VERSION 5.7 ;
BUSBITCHARS "[]" ;
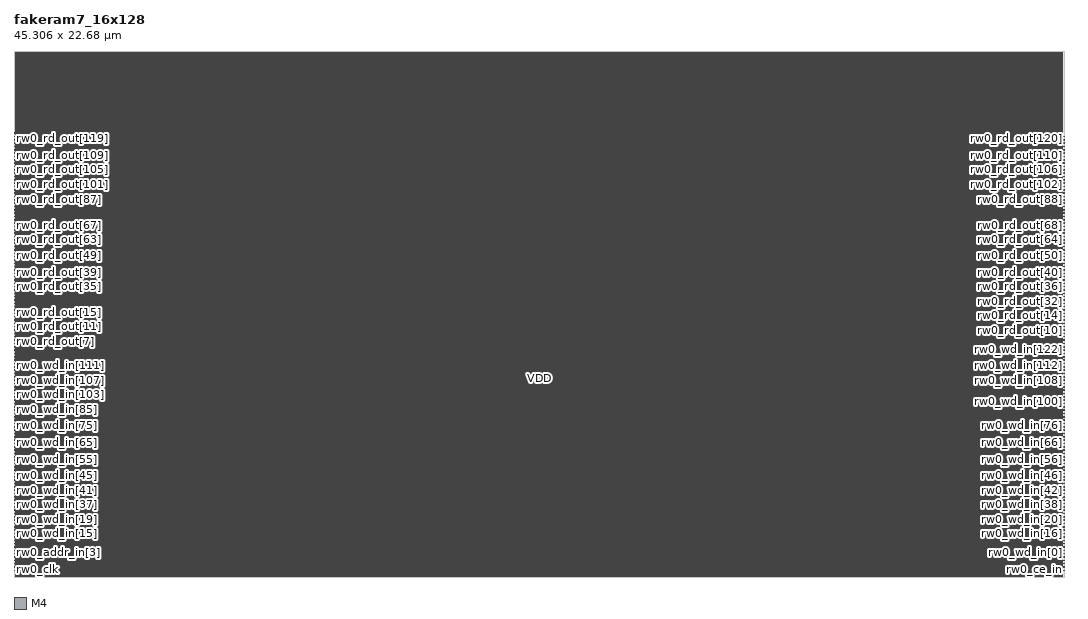
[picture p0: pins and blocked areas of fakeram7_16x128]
MACRO fakeram7_16x128
  FOREIGN fakeram7_16x128 0 0 ;
  SYMMETRY X Y R90 ;
  SIZE 45.306 BY 22.680 ;
  CLASS BLOCK ;
  PIN rw0_clk
    DIRECTION INPUT ;
    USE SIGNAL ;
    SHAPE ABUTMENT ;
    PORT
      LAYER M4 ;
      RECT 0.000 0.276 0.072 0.300 ;
    END
  END rw0_clk
  PIN rw0_ce_in
    DIRECTION INPUT ;
    USE SIGNAL ;
    SHAPE ABUTMENT ;
    PORT
      LAYER M4 ;
      RECT 45.234 0.276 45.306 0.300 ;
    END
  END rw0_ce_in
  PIN rw0_we_in
    DIRECTION INPUT ;
    USE SIGNAL ;
    SHAPE ABUTMENT ;
    PORT
      LAYER M4 ;
      RECT 0.000 0.420 0.072 0.444 ;
    END
  END rw0_we_in
  PIN rw0_addr_in[0]
    DIRECTION INPUT ;
    USE SIGNAL ;
    SHAPE ABUTMENT ;
    PORT
      LAYER M4 ;
      RECT 45.234 0.420 45.306 0.444 ;
    END
  END rw0_addr_in[0]
  PIN rw0_addr_in[1]
    DIRECTION INPUT ;
    USE SIGNAL ;
    SHAPE ABUTMENT ;
    PORT
      LAYER M4 ;
      RECT 0.000 0.564 0.072 0.588 ;
    END
  END rw0_addr_in[1]
  PIN rw0_addr_in[2]
    DIRECTION INPUT ;
    USE SIGNAL ;
    SHAPE ABUTMENT ;
    PORT
      LAYER M4 ;
      RECT 45.234 0.564 45.306 0.588 ;
    END
  END rw0_addr_in[2]
  PIN rw0_addr_in[3]
    DIRECTION INPUT ;
    USE SIGNAL ;
    SHAPE ABUTMENT ;
    PORT
      LAYER M4 ;
      RECT 0.000 0.708 0.072 0.732 ;
    END
  END rw0_addr_in[3]
  PIN rw0_wd_in[0]
    DIRECTION INPUT ;
    USE SIGNAL ;
    SHAPE ABUTMENT ;
    PORT
      LAYER M4 ;
      RECT 45.234 0.708 45.306 0.732 ;
    END
  END rw0_wd_in[0]
  PIN rw0_wd_in[1]
    DIRECTION INPUT ;
    USE SIGNAL ;
    SHAPE ABUTMENT ;
    PORT
      LAYER M4 ;
      RECT 0.000 0.852 0.072 0.876 ;
    END
  END rw0_wd_in[1]
  PIN rw0_wd_in[2]
    DIRECTION INPUT ;
    USE SIGNAL ;
    SHAPE ABUTMENT ;
    PORT
      LAYER M4 ;
      RECT 45.234 0.852 45.306 0.876 ;
    END
  END rw0_wd_in[2]
  PIN rw0_wd_in[3]
    DIRECTION INPUT ;
    USE SIGNAL ;
    SHAPE ABUTMENT ;
    PORT
      LAYER M4 ;
      RECT 0.000 0.996 0.072 1.020 ;
    END
  END rw0_wd_in[3]
  PIN rw0_wd_in[4]
    DIRECTION INPUT ;
    USE SIGNAL ;
    SHAPE ABUTMENT ;
    PORT
      LAYER M4 ;
      RECT 45.234 0.996 45.306 1.020 ;
    END
  END rw0_wd_in[4]
  PIN rw0_wd_in[5]
    DIRECTION INPUT ;
    USE SIGNAL ;
    SHAPE ABUTMENT ;
    PORT
      LAYER M4 ;
      RECT 0.000 1.140 0.072 1.164 ;
    END
  END rw0_wd_in[5]
  PIN rw0_wd_in[6]
    DIRECTION INPUT ;
    USE SIGNAL ;
    SHAPE ABUTMENT ;
    PORT
      LAYER M4 ;
      RECT 45.234 1.140 45.306 1.164 ;
    END
  END rw0_wd_in[6]
  PIN rw0_wd_in[7]
    DIRECTION INPUT ;
    USE SIGNAL ;
    SHAPE ABUTMENT ;
    PORT
      LAYER M4 ;
      RECT 0.000 1.284 0.072 1.308 ;
    END
  END rw0_wd_in[7]
  PIN rw0_wd_in[8]
    DIRECTION INPUT ;
    USE SIGNAL ;
    SHAPE ABUTMENT ;
    PORT
      LAYER M4 ;
      RECT 45.234 1.284 45.306 1.308 ;
    END
  END rw0_wd_in[8]
  PIN rw0_wd_in[9]
    DIRECTION INPUT ;
    USE SIGNAL ;
    SHAPE ABUTMENT ;
    PORT
      LAYER M4 ;
      RECT 0.000 1.428 0.072 1.452 ;
    END
  END rw0_wd_in[9]
  PIN rw0_wd_in[10]
    DIRECTION INPUT ;
    USE SIGNAL ;
    SHAPE ABUTMENT ;
    PORT
      LAYER M4 ;
      RECT 45.234 1.428 45.306 1.452 ;
    END
  END rw0_wd_in[10]
  PIN rw0_wd_in[11]
    DIRECTION INPUT ;
    USE SIGNAL ;
    SHAPE ABUTMENT ;
    PORT
      LAYER M4 ;
      RECT 0.000 1.572 0.072 1.596 ;
    END
  END rw0_wd_in[11]
  PIN rw0_wd_in[12]
    DIRECTION INPUT ;
    USE SIGNAL ;
    SHAPE ABUTMENT ;
    PORT
      LAYER M4 ;
      RECT 45.234 1.572 45.306 1.596 ;
    END
  END rw0_wd_in[12]
  PIN rw0_wd_in[13]
    DIRECTION INPUT ;
    USE SIGNAL ;
    SHAPE ABUTMENT ;
    PORT
      LAYER M4 ;
      RECT 0.000 1.716 0.072 1.740 ;
    END
  END rw0_wd_in[13]
  PIN rw0_wd_in[14]
    DIRECTION INPUT ;
    USE SIGNAL ;
    SHAPE ABUTMENT ;
    PORT
      LAYER M4 ;
      RECT 45.234 1.716 45.306 1.740 ;
    END
  END rw0_wd_in[14]
  PIN rw0_wd_in[15]
    DIRECTION INPUT ;
    USE SIGNAL ;
    SHAPE ABUTMENT ;
    PORT
      LAYER M4 ;
      RECT 0.000 1.860 0.072 1.884 ;
    END
  END rw0_wd_in[15]
  PIN rw0_wd_in[16]
    DIRECTION INPUT ;
    USE SIGNAL ;
    SHAPE ABUTMENT ;
    PORT
      LAYER M4 ;
      RECT 45.234 1.860 45.306 1.884 ;
    END
  END rw0_wd_in[16]
  PIN rw0_wd_in[17]
    DIRECTION INPUT ;
    USE SIGNAL ;
    SHAPE ABUTMENT ;
    PORT
      LAYER M4 ;
      RECT 0.000 2.004 0.072 2.028 ;
    END
  END rw0_wd_in[17]
  PIN rw0_wd_in[18]
    DIRECTION INPUT ;
    USE SIGNAL ;
    SHAPE ABUTMENT ;
    PORT
      LAYER M4 ;
      RECT 45.234 2.004 45.306 2.028 ;
    END
  END rw0_wd_in[18]
  PIN rw0_wd_in[19]
    DIRECTION INPUT ;
    USE SIGNAL ;
    SHAPE ABUTMENT ;
    PORT
      LAYER M4 ;
      RECT 0.000 2.148 0.072 2.172 ;
    END
  END rw0_wd_in[19]
  PIN rw0_wd_in[20]
    DIRECTION INPUT ;
    USE SIGNAL ;
    SHAPE ABUTMENT ;
    PORT
      LAYER M4 ;
      RECT 45.234 2.148 45.306 2.172 ;
    END
  END rw0_wd_in[20]
  PIN rw0_wd_in[21]
    DIRECTION INPUT ;
    USE SIGNAL ;
    SHAPE ABUTMENT ;
    PORT
      LAYER M4 ;
      RECT 0.000 2.292 0.072 2.316 ;
    END
  END rw0_wd_in[21]
  PIN rw0_wd_in[22]
    DIRECTION INPUT ;
    USE SIGNAL ;
    SHAPE ABUTMENT ;
    PORT
      LAYER M4 ;
      RECT 45.234 2.292 45.306 2.316 ;
    END
  END rw0_wd_in[22]
  PIN rw0_wd_in[23]
    DIRECTION INPUT ;
    USE SIGNAL ;
    SHAPE ABUTMENT ;
    PORT
      LAYER M4 ;
      RECT 0.000 2.436 0.072 2.460 ;
    END
  END rw0_wd_in[23]
  PIN rw0_wd_in[24]
    DIRECTION INPUT ;
    USE SIGNAL ;
    SHAPE ABUTMENT ;
    PORT
      LAYER M4 ;
      RECT 45.234 2.436 45.306 2.460 ;
    END
  END rw0_wd_in[24]
  PIN rw0_wd_in[25]
    DIRECTION INPUT ;
    USE SIGNAL ;
    SHAPE ABUTMENT ;
    PORT
      LAYER M4 ;
      RECT 0.000 2.580 0.072 2.604 ;
    END
  END rw0_wd_in[25]
  PIN rw0_wd_in[26]
    DIRECTION INPUT ;
    USE SIGNAL ;
    SHAPE ABUTMENT ;
    PORT
      LAYER M4 ;
      RECT 45.234 2.580 45.306 2.604 ;
    END
  END rw0_wd_in[26]
  PIN rw0_wd_in[27]
    DIRECTION INPUT ;
    USE SIGNAL ;
    SHAPE ABUTMENT ;
    PORT
      LAYER M4 ;
      RECT 0.000 2.724 0.072 2.748 ;
    END
  END rw0_wd_in[27]
  PIN rw0_wd_in[28]
    DIRECTION INPUT ;
    USE SIGNAL ;
    SHAPE ABUTMENT ;
    PORT
      LAYER M4 ;
      RECT 45.234 2.724 45.306 2.748 ;
    END
  END rw0_wd_in[28]
  PIN rw0_wd_in[29]
    DIRECTION INPUT ;
    USE SIGNAL ;
    SHAPE ABUTMENT ;
    PORT
      LAYER M4 ;
      RECT 0.000 2.868 0.072 2.892 ;
    END
  END rw0_wd_in[29]
  PIN rw0_wd_in[30]
    DIRECTION INPUT ;
    USE SIGNAL ;
    SHAPE ABUTMENT ;
    PORT
      LAYER M4 ;
      RECT 45.234 2.868 45.306 2.892 ;
    END
  END rw0_wd_in[30]
  PIN rw0_wd_in[31]
    DIRECTION INPUT ;
    USE SIGNAL ;
    SHAPE ABUTMENT ;
    PORT
      LAYER M4 ;
      RECT 0.000 3.012 0.072 3.036 ;
    END
  END rw0_wd_in[31]
  PIN rw0_wd_in[32]
    DIRECTION INPUT ;
    USE SIGNAL ;
    SHAPE ABUTMENT ;
    PORT
      LAYER M4 ;
      RECT 45.234 3.012 45.306 3.036 ;
    END
  END rw0_wd_in[32]
  PIN rw0_wd_in[33]
    DIRECTION INPUT ;
    USE SIGNAL ;
    SHAPE ABUTMENT ;
    PORT
      LAYER M4 ;
      RECT 0.000 3.156 0.072 3.180 ;
    END
  END rw0_wd_in[33]
  PIN rw0_wd_in[34]
    DIRECTION INPUT ;
    USE SIGNAL ;
    SHAPE ABUTMENT ;
    PORT
      LAYER M4 ;
      RECT 45.234 3.156 45.306 3.180 ;
    END
  END rw0_wd_in[34]
  PIN rw0_wd_in[35]
    DIRECTION INPUT ;
    USE SIGNAL ;
    SHAPE ABUTMENT ;
    PORT
      LAYER M4 ;
      RECT 0.000 3.300 0.072 3.324 ;
    END
  END rw0_wd_in[35]
  PIN rw0_wd_in[36]
    DIRECTION INPUT ;
    USE SIGNAL ;
    SHAPE ABUTMENT ;
    PORT
      LAYER M4 ;
      RECT 45.234 3.300 45.306 3.324 ;
    END
  END rw0_wd_in[36]
  PIN rw0_wd_in[37]
    DIRECTION INPUT ;
    USE SIGNAL ;
    SHAPE ABUTMENT ;
    PORT
      LAYER M4 ;
      RECT 0.000 3.444 0.072 3.468 ;
    END
  END rw0_wd_in[37]
  PIN rw0_wd_in[38]
    DIRECTION INPUT ;
    USE SIGNAL ;
    SHAPE ABUTMENT ;
    PORT
      LAYER M4 ;
      RECT 45.234 3.444 45.306 3.468 ;
    END
  END rw0_wd_in[38]
  PIN rw0_wd_in[39]
    DIRECTION INPUT ;
    USE SIGNAL ;
    SHAPE ABUTMENT ;
    PORT
      LAYER M4 ;
      RECT 0.000 3.588 0.072 3.612 ;
    END
  END rw0_wd_in[39]
  PIN rw0_wd_in[40]
    DIRECTION INPUT ;
    USE SIGNAL ;
    SHAPE ABUTMENT ;
    PORT
      LAYER M4 ;
      RECT 45.234 3.588 45.306 3.612 ;
    END
  END rw0_wd_in[40]
  PIN rw0_wd_in[41]
    DIRECTION INPUT ;
    USE SIGNAL ;
    SHAPE ABUTMENT ;
    PORT
      LAYER M4 ;
      RECT 0.000 3.732 0.072 3.756 ;
    END
  END rw0_wd_in[41]
  PIN rw0_wd_in[42]
    DIRECTION INPUT ;
    USE SIGNAL ;
    SHAPE ABUTMENT ;
    PORT
      LAYER M4 ;
      RECT 45.234 3.732 45.306 3.756 ;
    END
  END rw0_wd_in[42]
  PIN rw0_wd_in[43]
    DIRECTION INPUT ;
    USE SIGNAL ;
    SHAPE ABUTMENT ;
    PORT
      LAYER M4 ;
      RECT 0.000 3.876 0.072 3.900 ;
    END
  END rw0_wd_in[43]
  PIN rw0_wd_in[44]
    DIRECTION INPUT ;
    USE SIGNAL ;
    SHAPE ABUTMENT ;
    PORT
      LAYER M4 ;
      RECT 45.234 3.876 45.306 3.900 ;
    END
  END rw0_wd_in[44]
  PIN rw0_wd_in[45]
    DIRECTION INPUT ;
    USE SIGNAL ;
    SHAPE ABUTMENT ;
    PORT
      LAYER M4 ;
      RECT 0.000 4.020 0.072 4.044 ;
    END
  END rw0_wd_in[45]
  PIN rw0_wd_in[46]
    DIRECTION INPUT ;
    USE SIGNAL ;
    SHAPE ABUTMENT ;
    PORT
      LAYER M4 ;
      RECT 45.234 4.020 45.306 4.044 ;
    END
  END rw0_wd_in[46]
  PIN rw0_wd_in[47]
    DIRECTION INPUT ;
    USE SIGNAL ;
    SHAPE ABUTMENT ;
    PORT
      LAYER M4 ;
      RECT 0.000 4.164 0.072 4.188 ;
    END
  END rw0_wd_in[47]
  PIN rw0_wd_in[48]
    DIRECTION INPUT ;
    USE SIGNAL ;
    SHAPE ABUTMENT ;
    PORT
      LAYER M4 ;
      RECT 45.234 4.164 45.306 4.188 ;
    END
  END rw0_wd_in[48]
  PIN rw0_wd_in[49]
    DIRECTION INPUT ;
    USE SIGNAL ;
    SHAPE ABUTMENT ;
    PORT
      LAYER M4 ;
      RECT 0.000 4.308 0.072 4.332 ;
    END
  END rw0_wd_in[49]
  PIN rw0_wd_in[50]
    DIRECTION INPUT ;
    USE SIGNAL ;
    SHAPE ABUTMENT ;
    PORT
      LAYER M4 ;
      RECT 45.234 4.308 45.306 4.332 ;
    END
  END rw0_wd_in[50]
  PIN rw0_wd_in[51]
    DIRECTION INPUT ;
    USE SIGNAL ;
    SHAPE ABUTMENT ;
    PORT
      LAYER M4 ;
      RECT 0.000 4.452 0.072 4.476 ;
    END
  END rw0_wd_in[51]
  PIN rw0_wd_in[52]
    DIRECTION INPUT ;
    USE SIGNAL ;
    SHAPE ABUTMENT ;
    PORT
      LAYER M4 ;
      RECT 45.234 4.452 45.306 4.476 ;
    END
  END rw0_wd_in[52]
  PIN rw0_wd_in[53]
    DIRECTION INPUT ;
    USE SIGNAL ;
    SHAPE ABUTMENT ;
    PORT
      LAYER M4 ;
      RECT 0.000 4.596 0.072 4.620 ;
    END
  END rw0_wd_in[53]
  PIN rw0_wd_in[54]
    DIRECTION INPUT ;
    USE SIGNAL ;
    SHAPE ABUTMENT ;
    PORT
      LAYER M4 ;
      RECT 45.234 4.596 45.306 4.620 ;
    END
  END rw0_wd_in[54]
  PIN rw0_wd_in[55]
    DIRECTION INPUT ;
    USE SIGNAL ;
    SHAPE ABUTMENT ;
    PORT
      LAYER M4 ;
      RECT 0.000 4.740 0.072 4.764 ;
    END
  END rw0_wd_in[55]
  PIN rw0_wd_in[56]
    DIRECTION INPUT ;
    USE SIGNAL ;
    SHAPE ABUTMENT ;
    PORT
      LAYER M4 ;
      RECT 45.234 4.740 45.306 4.764 ;
    END
  END rw0_wd_in[56]
  PIN rw0_wd_in[57]
    DIRECTION INPUT ;
    USE SIGNAL ;
    SHAPE ABUTMENT ;
    PORT
      LAYER M4 ;
      RECT 0.000 4.884 0.072 4.908 ;
    END
  END rw0_wd_in[57]
  PIN rw0_wd_in[58]
    DIRECTION INPUT ;
    USE SIGNAL ;
    SHAPE ABUTMENT ;
    PORT
      LAYER M4 ;
      RECT 45.234 4.884 45.306 4.908 ;
    END
  END rw0_wd_in[58]
  PIN rw0_wd_in[59]
    DIRECTION INPUT ;
    USE SIGNAL ;
    SHAPE ABUTMENT ;
    PORT
      LAYER M4 ;
      RECT 0.000 5.028 0.072 5.052 ;
    END
  END rw0_wd_in[59]
  PIN rw0_wd_in[60]
    DIRECTION INPUT ;
    USE SIGNAL ;
    SHAPE ABUTMENT ;
    PORT
      LAYER M4 ;
      RECT 45.234 5.028 45.306 5.052 ;
    END
  END rw0_wd_in[60]
  PIN rw0_wd_in[61]
    DIRECTION INPUT ;
    USE SIGNAL ;
    SHAPE ABUTMENT ;
    PORT
      LAYER M4 ;
      RECT 0.000 5.172 0.072 5.196 ;
    END
  END rw0_wd_in[61]
  PIN rw0_wd_in[62]
    DIRECTION INPUT ;
    USE SIGNAL ;
    SHAPE ABUTMENT ;
    PORT
      LAYER M4 ;
      RECT 45.234 5.172 45.306 5.196 ;
    END
  END rw0_wd_in[62]
  PIN rw0_wd_in[63]
    DIRECTION INPUT ;
    USE SIGNAL ;
    SHAPE ABUTMENT ;
    PORT
      LAYER M4 ;
      RECT 0.000 5.316 0.072 5.340 ;
    END
  END rw0_wd_in[63]
  PIN rw0_wd_in[64]
    DIRECTION INPUT ;
    USE SIGNAL ;
    SHAPE ABUTMENT ;
    PORT
      LAYER M4 ;
      RECT 45.234 5.316 45.306 5.340 ;
    END
  END rw0_wd_in[64]
  PIN rw0_wd_in[65]
    DIRECTION INPUT ;
    USE SIGNAL ;
    SHAPE ABUTMENT ;
    PORT
      LAYER M4 ;
      RECT 0.000 5.460 0.072 5.484 ;
    END
  END rw0_wd_in[65]
  PIN rw0_wd_in[66]
    DIRECTION INPUT ;
    USE SIGNAL ;
    SHAPE ABUTMENT ;
    PORT
      LAYER M4 ;
      RECT 45.234 5.460 45.306 5.484 ;
    END
  END rw0_wd_in[66]
  PIN rw0_wd_in[67]
    DIRECTION INPUT ;
    USE SIGNAL ;
    SHAPE ABUTMENT ;
    PORT
      LAYER M4 ;
      RECT 0.000 5.604 0.072 5.628 ;
    END
  END rw0_wd_in[67]
  PIN rw0_wd_in[68]
    DIRECTION INPUT ;
    USE SIGNAL ;
    SHAPE ABUTMENT ;
    PORT
      LAYER M4 ;
      RECT 45.234 5.604 45.306 5.628 ;
    END
  END rw0_wd_in[68]
  PIN rw0_wd_in[69]
    DIRECTION INPUT ;
    USE SIGNAL ;
    SHAPE ABUTMENT ;
    PORT
      LAYER M4 ;
      RECT 0.000 5.748 0.072 5.772 ;
    END
  END rw0_wd_in[69]
  PIN rw0_wd_in[70]
    DIRECTION INPUT ;
    USE SIGNAL ;
    SHAPE ABUTMENT ;
    PORT
      LAYER M4 ;
      RECT 45.234 5.748 45.306 5.772 ;
    END
  END rw0_wd_in[70]
  PIN rw0_wd_in[71]
    DIRECTION INPUT ;
    USE SIGNAL ;
    SHAPE ABUTMENT ;
    PORT
      LAYER M4 ;
      RECT 0.000 5.892 0.072 5.916 ;
    END
  END rw0_wd_in[71]
  PIN rw0_wd_in[72]
    DIRECTION INPUT ;
    USE SIGNAL ;
    SHAPE ABUTMENT ;
    PORT
      LAYER M4 ;
      RECT 45.234 5.892 45.306 5.916 ;
    END
  END rw0_wd_in[72]
  PIN rw0_wd_in[73]
    DIRECTION INPUT ;
    USE SIGNAL ;
    SHAPE ABUTMENT ;
    PORT
      LAYER M4 ;
      RECT 0.000 6.036 0.072 6.060 ;
    END
  END rw0_wd_in[73]
  PIN rw0_wd_in[74]
    DIRECTION INPUT ;
    USE SIGNAL ;
    SHAPE ABUTMENT ;
    PORT
      LAYER M4 ;
      RECT 45.234 6.036 45.306 6.060 ;
    END
  END rw0_wd_in[74]
  PIN rw0_wd_in[75]
    DIRECTION INPUT ;
    USE SIGNAL ;
    SHAPE ABUTMENT ;
    PORT
      LAYER M4 ;
      RECT 0.000 6.180 0.072 6.204 ;
    END
  END rw0_wd_in[75]
  PIN rw0_wd_in[76]
    DIRECTION INPUT ;
    USE SIGNAL ;
    SHAPE ABUTMENT ;
    PORT
      LAYER M4 ;
      RECT 45.234 6.180 45.306 6.204 ;
    END
  END rw0_wd_in[76]
  PIN rw0_wd_in[77]
    DIRECTION INPUT ;
    USE SIGNAL ;
    SHAPE ABUTMENT ;
    PORT
      LAYER M4 ;
      RECT 0.000 6.324 0.072 6.348 ;
    END
  END rw0_wd_in[77]
  PIN rw0_wd_in[78]
    DIRECTION INPUT ;
    USE SIGNAL ;
    SHAPE ABUTMENT ;
    PORT
      LAYER M4 ;
      RECT 45.234 6.324 45.306 6.348 ;
    END
  END rw0_wd_in[78]
  PIN rw0_wd_in[79]
    DIRECTION INPUT ;
    USE SIGNAL ;
    SHAPE ABUTMENT ;
    PORT
      LAYER M4 ;
      RECT 0.000 6.468 0.072 6.492 ;
    END
  END rw0_wd_in[79]
  PIN rw0_wd_in[80]
    DIRECTION INPUT ;
    USE SIGNAL ;
    SHAPE ABUTMENT ;
    PORT
      LAYER M4 ;
      RECT 45.234 6.468 45.306 6.492 ;
    END
  END rw0_wd_in[80]
  PIN rw0_wd_in[81]
    DIRECTION INPUT ;
    USE SIGNAL ;
    SHAPE ABUTMENT ;
    PORT
      LAYER M4 ;
      RECT 0.000 6.612 0.072 6.636 ;
    END
  END rw0_wd_in[81]
  PIN rw0_wd_in[82]
    DIRECTION INPUT ;
    USE SIGNAL ;
    SHAPE ABUTMENT ;
    PORT
      LAYER M4 ;
      RECT 45.234 6.612 45.306 6.636 ;
    END
  END rw0_wd_in[82]
  PIN rw0_wd_in[83]
    DIRECTION INPUT ;
    USE SIGNAL ;
    SHAPE ABUTMENT ;
    PORT
      LAYER M4 ;
      RECT 0.000 6.756 0.072 6.780 ;
    END
  END rw0_wd_in[83]
  PIN rw0_wd_in[84]
    DIRECTION INPUT ;
    USE SIGNAL ;
    SHAPE ABUTMENT ;
    PORT
      LAYER M4 ;
      RECT 45.234 6.756 45.306 6.780 ;
    END
  END rw0_wd_in[84]
  PIN rw0_wd_in[85]
    DIRECTION INPUT ;
    USE SIGNAL ;
    SHAPE ABUTMENT ;
    PORT
      LAYER M4 ;
      RECT 0.000 6.900 0.072 6.924 ;
    END
  END rw0_wd_in[85]
  PIN rw0_wd_in[86]
    DIRECTION INPUT ;
    USE SIGNAL ;
    SHAPE ABUTMENT ;
    PORT
      LAYER M4 ;
      RECT 45.234 6.900 45.306 6.924 ;
    END
  END rw0_wd_in[86]
  PIN rw0_wd_in[87]
    DIRECTION INPUT ;
    USE SIGNAL ;
    SHAPE ABUTMENT ;
    PORT
      LAYER M4 ;
      RECT 0.000 7.044 0.072 7.068 ;
    END
  END rw0_wd_in[87]
  PIN rw0_wd_in[88]
    DIRECTION INPUT ;
    USE SIGNAL ;
    SHAPE ABUTMENT ;
    PORT
      LAYER M4 ;
      RECT 45.234 7.044 45.306 7.068 ;
    END
  END rw0_wd_in[88]
  PIN rw0_wd_in[89]
    DIRECTION INPUT ;
    USE SIGNAL ;
    SHAPE ABUTMENT ;
    PORT
      LAYER M4 ;
      RECT 0.000 7.188 0.072 7.212 ;
    END
  END rw0_wd_in[89]
  PIN rw0_wd_in[90]
    DIRECTION INPUT ;
    USE SIGNAL ;
    SHAPE ABUTMENT ;
    PORT
      LAYER M4 ;
      RECT 45.234 7.188 45.306 7.212 ;
    END
  END rw0_wd_in[90]
  PIN rw0_wd_in[91]
    DIRECTION INPUT ;
    USE SIGNAL ;
    SHAPE ABUTMENT ;
    PORT
      LAYER M4 ;
      RECT 0.000 7.332 0.072 7.356 ;
    END
  END rw0_wd_in[91]
  PIN rw0_wd_in[92]
    DIRECTION INPUT ;
    USE SIGNAL ;
    SHAPE ABUTMENT ;
    PORT
      LAYER M4 ;
      RECT 45.234 7.332 45.306 7.356 ;
    END
  END rw0_wd_in[92]
  PIN rw0_wd_in[93]
    DIRECTION INPUT ;
    USE SIGNAL ;
    SHAPE ABUTMENT ;
    PORT
      LAYER M4 ;
      RECT 0.000 7.476 0.072 7.500 ;
    END
  END rw0_wd_in[93]
  PIN rw0_wd_in[94]
    DIRECTION INPUT ;
    USE SIGNAL ;
    SHAPE ABUTMENT ;
    PORT
      LAYER M4 ;
      RECT 45.234 7.476 45.306 7.500 ;
    END
  END rw0_wd_in[94]
  PIN rw0_wd_in[95]
    DIRECTION INPUT ;
    USE SIGNAL ;
    SHAPE ABUTMENT ;
    PORT
      LAYER M4 ;
      RECT 0.000 7.620 0.072 7.644 ;
    END
  END rw0_wd_in[95]
  PIN rw0_wd_in[96]
    DIRECTION INPUT ;
    USE SIGNAL ;
    SHAPE ABUTMENT ;
    PORT
      LAYER M4 ;
      RECT 45.234 7.620 45.306 7.644 ;
    END
  END rw0_wd_in[96]
  PIN rw0_wd_in[97]
    DIRECTION INPUT ;
    USE SIGNAL ;
    SHAPE ABUTMENT ;
    PORT
      LAYER M4 ;
      RECT 0.000 7.764 0.072 7.788 ;
    END
  END rw0_wd_in[97]
  PIN rw0_wd_in[98]
    DIRECTION INPUT ;
    USE SIGNAL ;
    SHAPE ABUTMENT ;
    PORT
      LAYER M4 ;
      RECT 45.234 7.764 45.306 7.788 ;
    END
  END rw0_wd_in[98]
  PIN rw0_wd_in[99]
    DIRECTION INPUT ;
    USE SIGNAL ;
    SHAPE ABUTMENT ;
    PORT
      LAYER M4 ;
      RECT 0.000 7.908 0.072 7.932 ;
    END
  END rw0_wd_in[99]
  PIN rw0_wd_in[100]
    DIRECTION INPUT ;
    USE SIGNAL ;
    SHAPE ABUTMENT ;
    PORT
      LAYER M4 ;
      RECT 45.234 7.908 45.306 7.932 ;
    END
  END rw0_wd_in[100]
  PIN rw0_wd_in[101]
    DIRECTION INPUT ;
    USE SIGNAL ;
    SHAPE ABUTMENT ;
    PORT
      LAYER M4 ;
      RECT 0.000 8.052 0.072 8.076 ;
    END
  END rw0_wd_in[101]
  PIN rw0_wd_in[102]
    DIRECTION INPUT ;
    USE SIGNAL ;
    SHAPE ABUTMENT ;
    PORT
      LAYER M4 ;
      RECT 45.234 8.052 45.306 8.076 ;
    END
  END rw0_wd_in[102]
  PIN rw0_wd_in[103]
    DIRECTION INPUT ;
    USE SIGNAL ;
    SHAPE ABUTMENT ;
    PORT
      LAYER M4 ;
      RECT 0.000 8.196 0.072 8.220 ;
    END
  END rw0_wd_in[103]
  PIN rw0_wd_in[104]
    DIRECTION INPUT ;
    USE SIGNAL ;
    SHAPE ABUTMENT ;
    PORT
      LAYER M4 ;
      RECT 45.234 8.196 45.306 8.220 ;
    END
  END rw0_wd_in[104]
  PIN rw0_wd_in[105]
    DIRECTION INPUT ;
    USE SIGNAL ;
    SHAPE ABUTMENT ;
    PORT
      LAYER M4 ;
      RECT 0.000 8.340 0.072 8.364 ;
    END
  END rw0_wd_in[105]
  PIN rw0_wd_in[106]
    DIRECTION INPUT ;
    USE SIGNAL ;
    SHAPE ABUTMENT ;
    PORT
      LAYER M4 ;
      RECT 45.234 8.340 45.306 8.364 ;
    END
  END rw0_wd_in[106]
  PIN rw0_wd_in[107]
    DIRECTION INPUT ;
    USE SIGNAL ;
    SHAPE ABUTMENT ;
    PORT
      LAYER M4 ;
      RECT 0.000 8.484 0.072 8.508 ;
    END
  END rw0_wd_in[107]
  PIN rw0_wd_in[108]
    DIRECTION INPUT ;
    USE SIGNAL ;
    SHAPE ABUTMENT ;
    PORT
      LAYER M4 ;
      RECT 45.234 8.484 45.306 8.508 ;
    END
  END rw0_wd_in[108]
  PIN rw0_wd_in[109]
    DIRECTION INPUT ;
    USE SIGNAL ;
    SHAPE ABUTMENT ;
    PORT
      LAYER M4 ;
      RECT 0.000 8.628 0.072 8.652 ;
    END
  END rw0_wd_in[109]
  PIN rw0_wd_in[110]
    DIRECTION INPUT ;
    USE SIGNAL ;
    SHAPE ABUTMENT ;
    PORT
      LAYER M4 ;
      RECT 45.234 8.628 45.306 8.652 ;
    END
  END rw0_wd_in[110]
  PIN rw0_wd_in[111]
    DIRECTION INPUT ;
    USE SIGNAL ;
    SHAPE ABUTMENT ;
    PORT
      LAYER M4 ;
      RECT 0.000 8.772 0.072 8.796 ;
    END
  END rw0_wd_in[111]
  PIN rw0_wd_in[112]
    DIRECTION INPUT ;
    USE SIGNAL ;
    SHAPE ABUTMENT ;
    PORT
      LAYER M4 ;
      RECT 45.234 8.772 45.306 8.796 ;
    END
  END rw0_wd_in[112]
  PIN rw0_wd_in[113]
    DIRECTION INPUT ;
    USE SIGNAL ;
    SHAPE ABUTMENT ;
    PORT
      LAYER M4 ;
      RECT 0.000 8.916 0.072 8.940 ;
    END
  END rw0_wd_in[113]
  PIN rw0_wd_in[114]
    DIRECTION INPUT ;
    USE SIGNAL ;
    SHAPE ABUTMENT ;
    PORT
      LAYER M4 ;
      RECT 45.234 8.916 45.306 8.940 ;
    END
  END rw0_wd_in[114]
  PIN rw0_wd_in[115]
    DIRECTION INPUT ;
    USE SIGNAL ;
    SHAPE ABUTMENT ;
    PORT
      LAYER M4 ;
      RECT 0.000 9.060 0.072 9.084 ;
    END
  END rw0_wd_in[115]
  PIN rw0_wd_in[116]
    DIRECTION INPUT ;
    USE SIGNAL ;
    SHAPE ABUTMENT ;
    PORT
      LAYER M4 ;
      RECT 45.234 9.060 45.306 9.084 ;
    END
  END rw0_wd_in[116]
  PIN rw0_wd_in[117]
    DIRECTION INPUT ;
    USE SIGNAL ;
    SHAPE ABUTMENT ;
    PORT
      LAYER M4 ;
      RECT 0.000 9.204 0.072 9.228 ;
    END
  END rw0_wd_in[117]
  PIN rw0_wd_in[118]
    DIRECTION INPUT ;
    USE SIGNAL ;
    SHAPE ABUTMENT ;
    PORT
      LAYER M4 ;
      RECT 45.234 9.204 45.306 9.228 ;
    END
  END rw0_wd_in[118]
  PIN rw0_wd_in[119]
    DIRECTION INPUT ;
    USE SIGNAL ;
    SHAPE ABUTMENT ;
    PORT
      LAYER M4 ;
      RECT 0.000 9.348 0.072 9.372 ;
    END
  END rw0_wd_in[119]
  PIN rw0_wd_in[120]
    DIRECTION INPUT ;
    USE SIGNAL ;
    SHAPE ABUTMENT ;
    PORT
      LAYER M4 ;
      RECT 45.234 9.348 45.306 9.372 ;
    END
  END rw0_wd_in[120]
  PIN rw0_wd_in[121]
    DIRECTION INPUT ;
    USE SIGNAL ;
    SHAPE ABUTMENT ;
    PORT
      LAYER M4 ;
      RECT 0.000 9.492 0.072 9.516 ;
    END
  END rw0_wd_in[121]
  PIN rw0_wd_in[122]
    DIRECTION INPUT ;
    USE SIGNAL ;
    SHAPE ABUTMENT ;
    PORT
      LAYER M4 ;
      RECT 45.234 9.492 45.306 9.516 ;
    END
  END rw0_wd_in[122]
  PIN rw0_wd_in[123]
    DIRECTION INPUT ;
    USE SIGNAL ;
    SHAPE ABUTMENT ;
    PORT
      LAYER M4 ;
      RECT 0.000 9.636 0.072 9.660 ;
    END
  END rw0_wd_in[123]
  PIN rw0_wd_in[124]
    DIRECTION INPUT ;
    USE SIGNAL ;
    SHAPE ABUTMENT ;
    PORT
      LAYER M4 ;
      RECT 45.234 9.636 45.306 9.660 ;
    END
  END rw0_wd_in[124]
  PIN rw0_wd_in[125]
    DIRECTION INPUT ;
    USE SIGNAL ;
    SHAPE ABUTMENT ;
    PORT
      LAYER M4 ;
      RECT 0.000 9.780 0.072 9.804 ;
    END
  END rw0_wd_in[125]
  PIN rw0_wd_in[126]
    DIRECTION INPUT ;
    USE SIGNAL ;
    SHAPE ABUTMENT ;
    PORT
      LAYER M4 ;
      RECT 45.234 9.780 45.306 9.804 ;
    END
  END rw0_wd_in[126]
  PIN rw0_wd_in[127]
    DIRECTION INPUT ;
    USE SIGNAL ;
    SHAPE ABUTMENT ;
    PORT
      LAYER M4 ;
      RECT 0.000 9.924 0.072 9.948 ;
    END
  END rw0_wd_in[127]
  PIN rw0_rd_out[0]
    DIRECTION OUTPUT ;
    USE SIGNAL ;
    SHAPE ABUTMENT ;
    PORT
      LAYER M4 ;
      RECT 45.234 9.924 45.306 9.948 ;
    END
  END rw0_rd_out[0]
  PIN rw0_rd_out[1]
    DIRECTION OUTPUT ;
    USE SIGNAL ;
    SHAPE ABUTMENT ;
    PORT
      LAYER M4 ;
      RECT 0.000 10.068 0.072 10.092 ;
    END
  END rw0_rd_out[1]
  PIN rw0_rd_out[2]
    DIRECTION OUTPUT ;
    USE SIGNAL ;
    SHAPE ABUTMENT ;
    PORT
      LAYER M4 ;
      RECT 45.234 10.068 45.306 10.092 ;
    END
  END rw0_rd_out[2]
  PIN rw0_rd_out[3]
    DIRECTION OUTPUT ;
    USE SIGNAL ;
    SHAPE ABUTMENT ;
    PORT
      LAYER M4 ;
      RECT 0.000 10.212 0.072 10.236 ;
    END
  END rw0_rd_out[3]
  PIN rw0_rd_out[4]
    DIRECTION OUTPUT ;
    USE SIGNAL ;
    SHAPE ABUTMENT ;
    PORT
      LAYER M4 ;
      RECT 45.234 10.212 45.306 10.236 ;
    END
  END rw0_rd_out[4]
  PIN rw0_rd_out[5]
    DIRECTION OUTPUT ;
    USE SIGNAL ;
    SHAPE ABUTMENT ;
    PORT
      LAYER M4 ;
      RECT 0.000 10.356 0.072 10.380 ;
    END
  END rw0_rd_out[5]
  PIN rw0_rd_out[6]
    DIRECTION OUTPUT ;
    USE SIGNAL ;
    SHAPE ABUTMENT ;
    PORT
      LAYER M4 ;
      RECT 45.234 10.356 45.306 10.380 ;
    END
  END rw0_rd_out[6]
  PIN rw0_rd_out[7]
    DIRECTION OUTPUT ;
    USE SIGNAL ;
    SHAPE ABUTMENT ;
    PORT
      LAYER M4 ;
      RECT 0.000 10.500 0.072 10.524 ;
    END
  END rw0_rd_out[7]
  PIN rw0_rd_out[8]
    DIRECTION OUTPUT ;
    USE SIGNAL ;
    SHAPE ABUTMENT ;
    PORT
      LAYER M4 ;
      RECT 45.234 10.500 45.306 10.524 ;
    END
  END rw0_rd_out[8]
  PIN rw0_rd_out[9]
    DIRECTION OUTPUT ;
    USE SIGNAL ;
    SHAPE ABUTMENT ;
    PORT
      LAYER M4 ;
      RECT 0.000 10.644 0.072 10.668 ;
    END
  END rw0_rd_out[9]
  PIN rw0_rd_out[10]
    DIRECTION OUTPUT ;
    USE SIGNAL ;
    SHAPE ABUTMENT ;
    PORT
      LAYER M4 ;
      RECT 45.234 10.644 45.306 10.668 ;
    END
  END rw0_rd_out[10]
  PIN rw0_rd_out[11]
    DIRECTION OUTPUT ;
    USE SIGNAL ;
    SHAPE ABUTMENT ;
    PORT
      LAYER M4 ;
      RECT 0.000 10.788 0.072 10.812 ;
    END
  END rw0_rd_out[11]
  PIN rw0_rd_out[12]
    DIRECTION OUTPUT ;
    USE SIGNAL ;
    SHAPE ABUTMENT ;
    PORT
      LAYER M4 ;
      RECT 45.234 10.788 45.306 10.812 ;
    END
  END rw0_rd_out[12]
  PIN rw0_rd_out[13]
    DIRECTION OUTPUT ;
    USE SIGNAL ;
    SHAPE ABUTMENT ;
    PORT
      LAYER M4 ;
      RECT 0.000 10.932 0.072 10.956 ;
    END
  END rw0_rd_out[13]
  PIN rw0_rd_out[14]
    DIRECTION OUTPUT ;
    USE SIGNAL ;
    SHAPE ABUTMENT ;
    PORT
      LAYER M4 ;
      RECT 45.234 10.932 45.306 10.956 ;
    END
  END rw0_rd_out[14]
  PIN rw0_rd_out[15]
    DIRECTION OUTPUT ;
    USE SIGNAL ;
    SHAPE ABUTMENT ;
    PORT
      LAYER M4 ;
      RECT 0.000 11.076 0.072 11.100 ;
    END
  END rw0_rd_out[15]
  PIN rw0_rd_out[16]
    DIRECTION OUTPUT ;
    USE SIGNAL ;
    SHAPE ABUTMENT ;
    PORT
      LAYER M4 ;
      RECT 45.234 11.076 45.306 11.100 ;
    END
  END rw0_rd_out[16]
  PIN rw0_rd_out[17]
    DIRECTION OUTPUT ;
    USE SIGNAL ;
    SHAPE ABUTMENT ;
    PORT
      LAYER M4 ;
      RECT 0.000 11.220 0.072 11.244 ;
    END
  END rw0_rd_out[17]
  PIN rw0_rd_out[18]
    DIRECTION OUTPUT ;
    USE SIGNAL ;
    SHAPE ABUTMENT ;
    PORT
      LAYER M4 ;
      RECT 45.234 11.220 45.306 11.244 ;
    END
  END rw0_rd_out[18]
  PIN rw0_rd_out[19]
    DIRECTION OUTPUT ;
    USE SIGNAL ;
    SHAPE ABUTMENT ;
    PORT
      LAYER M4 ;
      RECT 0.000 11.364 0.072 11.388 ;
    END
  END rw0_rd_out[19]
  PIN rw0_rd_out[20]
    DIRECTION OUTPUT ;
    USE SIGNAL ;
    SHAPE ABUTMENT ;
    PORT
      LAYER M4 ;
      RECT 45.234 11.364 45.306 11.388 ;
    END
  END rw0_rd_out[20]
  PIN rw0_rd_out[21]
    DIRECTION OUTPUT ;
    USE SIGNAL ;
    SHAPE ABUTMENT ;
    PORT
      LAYER M4 ;
      RECT 0.000 11.508 0.072 11.532 ;
    END
  END rw0_rd_out[21]
  PIN rw0_rd_out[22]
    DIRECTION OUTPUT ;
    USE SIGNAL ;
    SHAPE ABUTMENT ;
    PORT
      LAYER M4 ;
      RECT 45.234 11.508 45.306 11.532 ;
    END
  END rw0_rd_out[22]
  PIN rw0_rd_out[23]
    DIRECTION OUTPUT ;
    USE SIGNAL ;
    SHAPE ABUTMENT ;
    PORT
      LAYER M4 ;
      RECT 0.000 11.652 0.072 11.676 ;
    END
  END rw0_rd_out[23]
  PIN rw0_rd_out[24]
    DIRECTION OUTPUT ;
    USE SIGNAL ;
    SHAPE ABUTMENT ;
    PORT
      LAYER M4 ;
      RECT 45.234 11.652 45.306 11.676 ;
    END
  END rw0_rd_out[24]
  PIN rw0_rd_out[25]
    DIRECTION OUTPUT ;
    USE SIGNAL ;
    SHAPE ABUTMENT ;
    PORT
      LAYER M4 ;
      RECT 0.000 11.796 0.072 11.820 ;
    END
  END rw0_rd_out[25]
  PIN rw0_rd_out[26]
    DIRECTION OUTPUT ;
    USE SIGNAL ;
    SHAPE ABUTMENT ;
    PORT
      LAYER M4 ;
      RECT 45.234 11.796 45.306 11.820 ;
    END
  END rw0_rd_out[26]
  PIN rw0_rd_out[27]
    DIRECTION OUTPUT ;
    USE SIGNAL ;
    SHAPE ABUTMENT ;
    PORT
      LAYER M4 ;
      RECT 0.000 11.940 0.072 11.964 ;
    END
  END rw0_rd_out[27]
  PIN rw0_rd_out[28]
    DIRECTION OUTPUT ;
    USE SIGNAL ;
    SHAPE ABUTMENT ;
    PORT
      LAYER M4 ;
      RECT 45.234 11.940 45.306 11.964 ;
    END
  END rw0_rd_out[28]
  PIN rw0_rd_out[29]
    DIRECTION OUTPUT ;
    USE SIGNAL ;
    SHAPE ABUTMENT ;
    PORT
      LAYER M4 ;
      RECT 0.000 12.084 0.072 12.108 ;
    END
  END rw0_rd_out[29]
  PIN rw0_rd_out[30]
    DIRECTION OUTPUT ;
    USE SIGNAL ;
    SHAPE ABUTMENT ;
    PORT
      LAYER M4 ;
      RECT 45.234 12.084 45.306 12.108 ;
    END
  END rw0_rd_out[30]
  PIN rw0_rd_out[31]
    DIRECTION OUTPUT ;
    USE SIGNAL ;
    SHAPE ABUTMENT ;
    PORT
      LAYER M4 ;
      RECT 0.000 12.228 0.072 12.252 ;
    END
  END rw0_rd_out[31]
  PIN rw0_rd_out[32]
    DIRECTION OUTPUT ;
    USE SIGNAL ;
    SHAPE ABUTMENT ;
    PORT
      LAYER M4 ;
      RECT 45.234 12.228 45.306 12.252 ;
    END
  END rw0_rd_out[32]
  PIN rw0_rd_out[33]
    DIRECTION OUTPUT ;
    USE SIGNAL ;
    SHAPE ABUTMENT ;
    PORT
      LAYER M4 ;
      RECT 0.000 12.372 0.072 12.396 ;
    END
  END rw0_rd_out[33]
  PIN rw0_rd_out[34]
    DIRECTION OUTPUT ;
    USE SIGNAL ;
    SHAPE ABUTMENT ;
    PORT
      LAYER M4 ;
      RECT 45.234 12.372 45.306 12.396 ;
    END
  END rw0_rd_out[34]
  PIN rw0_rd_out[35]
    DIRECTION OUTPUT ;
    USE SIGNAL ;
    SHAPE ABUTMENT ;
    PORT
      LAYER M4 ;
      RECT 0.000 12.516 0.072 12.540 ;
    END
  END rw0_rd_out[35]
  PIN rw0_rd_out[36]
    DIRECTION OUTPUT ;
    USE SIGNAL ;
    SHAPE ABUTMENT ;
    PORT
      LAYER M4 ;
      RECT 45.234 12.516 45.306 12.540 ;
    END
  END rw0_rd_out[36]
  PIN rw0_rd_out[37]
    DIRECTION OUTPUT ;
    USE SIGNAL ;
    SHAPE ABUTMENT ;
    PORT
      LAYER M4 ;
      RECT 0.000 12.660 0.072 12.684 ;
    END
  END rw0_rd_out[37]
  PIN rw0_rd_out[38]
    DIRECTION OUTPUT ;
    USE SIGNAL ;
    SHAPE ABUTMENT ;
    PORT
      LAYER M4 ;
      RECT 45.234 12.660 45.306 12.684 ;
    END
  END rw0_rd_out[38]
  PIN rw0_rd_out[39]
    DIRECTION OUTPUT ;
    USE SIGNAL ;
    SHAPE ABUTMENT ;
    PORT
      LAYER M4 ;
      RECT 0.000 12.804 0.072 12.828 ;
    END
  END rw0_rd_out[39]
  PIN rw0_rd_out[40]
    DIRECTION OUTPUT ;
    USE SIGNAL ;
    SHAPE ABUTMENT ;
    PORT
      LAYER M4 ;
      RECT 45.234 12.804 45.306 12.828 ;
    END
  END rw0_rd_out[40]
  PIN rw0_rd_out[41]
    DIRECTION OUTPUT ;
    USE SIGNAL ;
    SHAPE ABUTMENT ;
    PORT
      LAYER M4 ;
      RECT 0.000 12.948 0.072 12.972 ;
    END
  END rw0_rd_out[41]
  PIN rw0_rd_out[42]
    DIRECTION OUTPUT ;
    USE SIGNAL ;
    SHAPE ABUTMENT ;
    PORT
      LAYER M4 ;
      RECT 45.234 12.948 45.306 12.972 ;
    END
  END rw0_rd_out[42]
  PIN rw0_rd_out[43]
    DIRECTION OUTPUT ;
    USE SIGNAL ;
    SHAPE ABUTMENT ;
    PORT
      LAYER M4 ;
      RECT 0.000 13.092 0.072 13.116 ;
    END
  END rw0_rd_out[43]
  PIN rw0_rd_out[44]
    DIRECTION OUTPUT ;
    USE SIGNAL ;
    SHAPE ABUTMENT ;
    PORT
      LAYER M4 ;
      RECT 45.234 13.092 45.306 13.116 ;
    END
  END rw0_rd_out[44]
  PIN rw0_rd_out[45]
    DIRECTION OUTPUT ;
    USE SIGNAL ;
    SHAPE ABUTMENT ;
    PORT
      LAYER M4 ;
      RECT 0.000 13.236 0.072 13.260 ;
    END
  END rw0_rd_out[45]
  PIN rw0_rd_out[46]
    DIRECTION OUTPUT ;
    USE SIGNAL ;
    SHAPE ABUTMENT ;
    PORT
      LAYER M4 ;
      RECT 45.234 13.236 45.306 13.260 ;
    END
  END rw0_rd_out[46]
  PIN rw0_rd_out[47]
    DIRECTION OUTPUT ;
    USE SIGNAL ;
    SHAPE ABUTMENT ;
    PORT
      LAYER M4 ;
      RECT 0.000 13.380 0.072 13.404 ;
    END
  END rw0_rd_out[47]
  PIN rw0_rd_out[48]
    DIRECTION OUTPUT ;
    USE SIGNAL ;
    SHAPE ABUTMENT ;
    PORT
      LAYER M4 ;
      RECT 45.234 13.380 45.306 13.404 ;
    END
  END rw0_rd_out[48]
  PIN rw0_rd_out[49]
    DIRECTION OUTPUT ;
    USE SIGNAL ;
    SHAPE ABUTMENT ;
    PORT
      LAYER M4 ;
      RECT 0.000 13.524 0.072 13.548 ;
    END
  END rw0_rd_out[49]
  PIN rw0_rd_out[50]
    DIRECTION OUTPUT ;
    USE SIGNAL ;
    SHAPE ABUTMENT ;
    PORT
      LAYER M4 ;
      RECT 45.234 13.524 45.306 13.548 ;
    END
  END rw0_rd_out[50]
  PIN rw0_rd_out[51]
    DIRECTION OUTPUT ;
    USE SIGNAL ;
    SHAPE ABUTMENT ;
    PORT
      LAYER M4 ;
      RECT 0.000 13.668 0.072 13.692 ;
    END
  END rw0_rd_out[51]
  PIN rw0_rd_out[52]
    DIRECTION OUTPUT ;
    USE SIGNAL ;
    SHAPE ABUTMENT ;
    PORT
      LAYER M4 ;
      RECT 45.234 13.668 45.306 13.692 ;
    END
  END rw0_rd_out[52]
  PIN rw0_rd_out[53]
    DIRECTION OUTPUT ;
    USE SIGNAL ;
    SHAPE ABUTMENT ;
    PORT
      LAYER M4 ;
      RECT 0.000 13.812 0.072 13.836 ;
    END
  END rw0_rd_out[53]
  PIN rw0_rd_out[54]
    DIRECTION OUTPUT ;
    USE SIGNAL ;
    SHAPE ABUTMENT ;
    PORT
      LAYER M4 ;
      RECT 45.234 13.812 45.306 13.836 ;
    END
  END rw0_rd_out[54]
  PIN rw0_rd_out[55]
    DIRECTION OUTPUT ;
    USE SIGNAL ;
    SHAPE ABUTMENT ;
    PORT
      LAYER M4 ;
      RECT 0.000 13.956 0.072 13.980 ;
    END
  END rw0_rd_out[55]
  PIN rw0_rd_out[56]
    DIRECTION OUTPUT ;
    USE SIGNAL ;
    SHAPE ABUTMENT ;
    PORT
      LAYER M4 ;
      RECT 45.234 13.956 45.306 13.980 ;
    END
  END rw0_rd_out[56]
  PIN rw0_rd_out[57]
    DIRECTION OUTPUT ;
    USE SIGNAL ;
    SHAPE ABUTMENT ;
    PORT
      LAYER M4 ;
      RECT 0.000 14.100 0.072 14.124 ;
    END
  END rw0_rd_out[57]
  PIN rw0_rd_out[58]
    DIRECTION OUTPUT ;
    USE SIGNAL ;
    SHAPE ABUTMENT ;
    PORT
      LAYER M4 ;
      RECT 45.234 14.100 45.306 14.124 ;
    END
  END rw0_rd_out[58]
  PIN rw0_rd_out[59]
    DIRECTION OUTPUT ;
    USE SIGNAL ;
    SHAPE ABUTMENT ;
    PORT
      LAYER M4 ;
      RECT 0.000 14.244 0.072 14.268 ;
    END
  END rw0_rd_out[59]
  PIN rw0_rd_out[60]
    DIRECTION OUTPUT ;
    USE SIGNAL ;
    SHAPE ABUTMENT ;
    PORT
      LAYER M4 ;
      RECT 45.234 14.244 45.306 14.268 ;
    END
  END rw0_rd_out[60]
  PIN rw0_rd_out[61]
    DIRECTION OUTPUT ;
    USE SIGNAL ;
    SHAPE ABUTMENT ;
    PORT
      LAYER M4 ;
      RECT 0.000 14.388 0.072 14.412 ;
    END
  END rw0_rd_out[61]
  PIN rw0_rd_out[62]
    DIRECTION OUTPUT ;
    USE SIGNAL ;
    SHAPE ABUTMENT ;
    PORT
      LAYER M4 ;
      RECT 45.234 14.388 45.306 14.412 ;
    END
  END rw0_rd_out[62]
  PIN rw0_rd_out[63]
    DIRECTION OUTPUT ;
    USE SIGNAL ;
    SHAPE ABUTMENT ;
    PORT
      LAYER M4 ;
      RECT 0.000 14.532 0.072 14.556 ;
    END
  END rw0_rd_out[63]
  PIN rw0_rd_out[64]
    DIRECTION OUTPUT ;
    USE SIGNAL ;
    SHAPE ABUTMENT ;
    PORT
      LAYER M4 ;
      RECT 45.234 14.532 45.306 14.556 ;
    END
  END rw0_rd_out[64]
  PIN rw0_rd_out[65]
    DIRECTION OUTPUT ;
    USE SIGNAL ;
    SHAPE ABUTMENT ;
    PORT
      LAYER M4 ;
      RECT 0.000 14.676 0.072 14.700 ;
    END
  END rw0_rd_out[65]
  PIN rw0_rd_out[66]
    DIRECTION OUTPUT ;
    USE SIGNAL ;
    SHAPE ABUTMENT ;
    PORT
      LAYER M4 ;
      RECT 45.234 14.676 45.306 14.700 ;
    END
  END rw0_rd_out[66]
  PIN rw0_rd_out[67]
    DIRECTION OUTPUT ;
    USE SIGNAL ;
    SHAPE ABUTMENT ;
    PORT
      LAYER M4 ;
      RECT 0.000 14.820 0.072 14.844 ;
    END
  END rw0_rd_out[67]
  PIN rw0_rd_out[68]
    DIRECTION OUTPUT ;
    USE SIGNAL ;
    SHAPE ABUTMENT ;
    PORT
      LAYER M4 ;
      RECT 45.234 14.820 45.306 14.844 ;
    END
  END rw0_rd_out[68]
  PIN rw0_rd_out[69]
    DIRECTION OUTPUT ;
    USE SIGNAL ;
    SHAPE ABUTMENT ;
    PORT
      LAYER M4 ;
      RECT 0.000 14.964 0.072 14.988 ;
    END
  END rw0_rd_out[69]
  PIN rw0_rd_out[70]
    DIRECTION OUTPUT ;
    USE SIGNAL ;
    SHAPE ABUTMENT ;
    PORT
      LAYER M4 ;
      RECT 45.234 14.964 45.306 14.988 ;
    END
  END rw0_rd_out[70]
  PIN rw0_rd_out[71]
    DIRECTION OUTPUT ;
    USE SIGNAL ;
    SHAPE ABUTMENT ;
    PORT
      LAYER M4 ;
      RECT 0.000 15.108 0.072 15.132 ;
    END
  END rw0_rd_out[71]
  PIN rw0_rd_out[72]
    DIRECTION OUTPUT ;
    USE SIGNAL ;
    SHAPE ABUTMENT ;
    PORT
      LAYER M4 ;
      RECT 45.234 15.108 45.306 15.132 ;
    END
  END rw0_rd_out[72]
  PIN rw0_rd_out[73]
    DIRECTION OUTPUT ;
    USE SIGNAL ;
    SHAPE ABUTMENT ;
    PORT
      LAYER M4 ;
      RECT 0.000 15.252 0.072 15.276 ;
    END
  END rw0_rd_out[73]
  PIN rw0_rd_out[74]
    DIRECTION OUTPUT ;
    USE SIGNAL ;
    SHAPE ABUTMENT ;
    PORT
      LAYER M4 ;
      RECT 45.234 15.252 45.306 15.276 ;
    END
  END rw0_rd_out[74]
  PIN rw0_rd_out[75]
    DIRECTION OUTPUT ;
    USE SIGNAL ;
    SHAPE ABUTMENT ;
    PORT
      LAYER M4 ;
      RECT 0.000 15.396 0.072 15.420 ;
    END
  END rw0_rd_out[75]
  PIN rw0_rd_out[76]
    DIRECTION OUTPUT ;
    USE SIGNAL ;
    SHAPE ABUTMENT ;
    PORT
      LAYER M4 ;
      RECT 45.234 15.396 45.306 15.420 ;
    END
  END rw0_rd_out[76]
  PIN rw0_rd_out[77]
    DIRECTION OUTPUT ;
    USE SIGNAL ;
    SHAPE ABUTMENT ;
    PORT
      LAYER M4 ;
      RECT 0.000 15.540 0.072 15.564 ;
    END
  END rw0_rd_out[77]
  PIN rw0_rd_out[78]
    DIRECTION OUTPUT ;
    USE SIGNAL ;
    SHAPE ABUTMENT ;
    PORT
      LAYER M4 ;
      RECT 45.234 15.540 45.306 15.564 ;
    END
  END rw0_rd_out[78]
  PIN rw0_rd_out[79]
    DIRECTION OUTPUT ;
    USE SIGNAL ;
    SHAPE ABUTMENT ;
    PORT
      LAYER M4 ;
      RECT 0.000 15.684 0.072 15.708 ;
    END
  END rw0_rd_out[79]
  PIN rw0_rd_out[80]
    DIRECTION OUTPUT ;
    USE SIGNAL ;
    SHAPE ABUTMENT ;
    PORT
      LAYER M4 ;
      RECT 45.234 15.684 45.306 15.708 ;
    END
  END rw0_rd_out[80]
  PIN rw0_rd_out[81]
    DIRECTION OUTPUT ;
    USE SIGNAL ;
    SHAPE ABUTMENT ;
    PORT
      LAYER M4 ;
      RECT 0.000 15.828 0.072 15.852 ;
    END
  END rw0_rd_out[81]
  PIN rw0_rd_out[82]
    DIRECTION OUTPUT ;
    USE SIGNAL ;
    SHAPE ABUTMENT ;
    PORT
      LAYER M4 ;
      RECT 45.234 15.828 45.306 15.852 ;
    END
  END rw0_rd_out[82]
  PIN rw0_rd_out[83]
    DIRECTION OUTPUT ;
    USE SIGNAL ;
    SHAPE ABUTMENT ;
    PORT
      LAYER M4 ;
      RECT 0.000 15.972 0.072 15.996 ;
    END
  END rw0_rd_out[83]
  PIN rw0_rd_out[84]
    DIRECTION OUTPUT ;
    USE SIGNAL ;
    SHAPE ABUTMENT ;
    PORT
      LAYER M4 ;
      RECT 45.234 15.972 45.306 15.996 ;
    END
  END rw0_rd_out[84]
  PIN rw0_rd_out[85]
    DIRECTION OUTPUT ;
    USE SIGNAL ;
    SHAPE ABUTMENT ;
    PORT
      LAYER M4 ;
      RECT 0.000 16.116 0.072 16.140 ;
    END
  END rw0_rd_out[85]
  PIN rw0_rd_out[86]
    DIRECTION OUTPUT ;
    USE SIGNAL ;
    SHAPE ABUTMENT ;
    PORT
      LAYER M4 ;
      RECT 45.234 16.116 45.306 16.140 ;
    END
  END rw0_rd_out[86]
  PIN rw0_rd_out[87]
    DIRECTION OUTPUT ;
    USE SIGNAL ;
    SHAPE ABUTMENT ;
    PORT
      LAYER M4 ;
      RECT 0.000 16.260 0.072 16.284 ;
    END
  END rw0_rd_out[87]
  PIN rw0_rd_out[88]
    DIRECTION OUTPUT ;
    USE SIGNAL ;
    SHAPE ABUTMENT ;
    PORT
      LAYER M4 ;
      RECT 45.234 16.260 45.306 16.284 ;
    END
  END rw0_rd_out[88]
  PIN rw0_rd_out[89]
    DIRECTION OUTPUT ;
    USE SIGNAL ;
    SHAPE ABUTMENT ;
    PORT
      LAYER M4 ;
      RECT 0.000 16.404 0.072 16.428 ;
    END
  END rw0_rd_out[89]
  PIN rw0_rd_out[90]
    DIRECTION OUTPUT ;
    USE SIGNAL ;
    SHAPE ABUTMENT ;
    PORT
      LAYER M4 ;
      RECT 45.234 16.404 45.306 16.428 ;
    END
  END rw0_rd_out[90]
  PIN rw0_rd_out[91]
    DIRECTION OUTPUT ;
    USE SIGNAL ;
    SHAPE ABUTMENT ;
    PORT
      LAYER M4 ;
      RECT 0.000 16.548 0.072 16.572 ;
    END
  END rw0_rd_out[91]
  PIN rw0_rd_out[92]
    DIRECTION OUTPUT ;
    USE SIGNAL ;
    SHAPE ABUTMENT ;
    PORT
      LAYER M4 ;
      RECT 45.234 16.548 45.306 16.572 ;
    END
  END rw0_rd_out[92]
  PIN rw0_rd_out[93]
    DIRECTION OUTPUT ;
    USE SIGNAL ;
    SHAPE ABUTMENT ;
    PORT
      LAYER M4 ;
      RECT 0.000 16.692 0.072 16.716 ;
    END
  END rw0_rd_out[93]
  PIN rw0_rd_out[94]
    DIRECTION OUTPUT ;
    USE SIGNAL ;
    SHAPE ABUTMENT ;
    PORT
      LAYER M4 ;
      RECT 45.234 16.692 45.306 16.716 ;
    END
  END rw0_rd_out[94]
  PIN rw0_rd_out[95]
    DIRECTION OUTPUT ;
    USE SIGNAL ;
    SHAPE ABUTMENT ;
    PORT
      LAYER M4 ;
      RECT 0.000 16.836 0.072 16.860 ;
    END
  END rw0_rd_out[95]
  PIN rw0_rd_out[96]
    DIRECTION OUTPUT ;
    USE SIGNAL ;
    SHAPE ABUTMENT ;
    PORT
      LAYER M4 ;
      RECT 45.234 16.836 45.306 16.860 ;
    END
  END rw0_rd_out[96]
  PIN rw0_rd_out[97]
    DIRECTION OUTPUT ;
    USE SIGNAL ;
    SHAPE ABUTMENT ;
    PORT
      LAYER M4 ;
      RECT 0.000 16.980 0.072 17.004 ;
    END
  END rw0_rd_out[97]
  PIN rw0_rd_out[98]
    DIRECTION OUTPUT ;
    USE SIGNAL ;
    SHAPE ABUTMENT ;
    PORT
      LAYER M4 ;
      RECT 45.234 16.980 45.306 17.004 ;
    END
  END rw0_rd_out[98]
  PIN rw0_rd_out[99]
    DIRECTION OUTPUT ;
    USE SIGNAL ;
    SHAPE ABUTMENT ;
    PORT
      LAYER M4 ;
      RECT 0.000 17.124 0.072 17.148 ;
    END
  END rw0_rd_out[99]
  PIN rw0_rd_out[100]
    DIRECTION OUTPUT ;
    USE SIGNAL ;
    SHAPE ABUTMENT ;
    PORT
      LAYER M4 ;
      RECT 45.234 17.124 45.306 17.148 ;
    END
  END rw0_rd_out[100]
  PIN rw0_rd_out[101]
    DIRECTION OUTPUT ;
    USE SIGNAL ;
    SHAPE ABUTMENT ;
    PORT
      LAYER M4 ;
      RECT 0.000 17.268 0.072 17.292 ;
    END
  END rw0_rd_out[101]
  PIN rw0_rd_out[102]
    DIRECTION OUTPUT ;
    USE SIGNAL ;
    SHAPE ABUTMENT ;
    PORT
      LAYER M4 ;
      RECT 45.234 17.268 45.306 17.292 ;
    END
  END rw0_rd_out[102]
  PIN rw0_rd_out[103]
    DIRECTION OUTPUT ;
    USE SIGNAL ;
    SHAPE ABUTMENT ;
    PORT
      LAYER M4 ;
      RECT 0.000 17.412 0.072 17.436 ;
    END
  END rw0_rd_out[103]
  PIN rw0_rd_out[104]
    DIRECTION OUTPUT ;
    USE SIGNAL ;
    SHAPE ABUTMENT ;
    PORT
      LAYER M4 ;
      RECT 45.234 17.412 45.306 17.436 ;
    END
  END rw0_rd_out[104]
  PIN rw0_rd_out[105]
    DIRECTION OUTPUT ;
    USE SIGNAL ;
    SHAPE ABUTMENT ;
    PORT
      LAYER M4 ;
      RECT 0.000 17.556 0.072 17.580 ;
    END
  END rw0_rd_out[105]
  PIN rw0_rd_out[106]
    DIRECTION OUTPUT ;
    USE SIGNAL ;
    SHAPE ABUTMENT ;
    PORT
      LAYER M4 ;
      RECT 45.234 17.556 45.306 17.580 ;
    END
  END rw0_rd_out[106]
  PIN rw0_rd_out[107]
    DIRECTION OUTPUT ;
    USE SIGNAL ;
    SHAPE ABUTMENT ;
    PORT
      LAYER M4 ;
      RECT 0.000 17.700 0.072 17.724 ;
    END
  END rw0_rd_out[107]
  PIN rw0_rd_out[108]
    DIRECTION OUTPUT ;
    USE SIGNAL ;
    SHAPE ABUTMENT ;
    PORT
      LAYER M4 ;
      RECT 45.234 17.700 45.306 17.724 ;
    END
  END rw0_rd_out[108]
  PIN rw0_rd_out[109]
    DIRECTION OUTPUT ;
    USE SIGNAL ;
    SHAPE ABUTMENT ;
    PORT
      LAYER M4 ;
      RECT 0.000 17.844 0.072 17.868 ;
    END
  END rw0_rd_out[109]
  PIN rw0_rd_out[110]
    DIRECTION OUTPUT ;
    USE SIGNAL ;
    SHAPE ABUTMENT ;
    PORT
      LAYER M4 ;
      RECT 45.234 17.844 45.306 17.868 ;
    END
  END rw0_rd_out[110]
  PIN rw0_rd_out[111]
    DIRECTION OUTPUT ;
    USE SIGNAL ;
    SHAPE ABUTMENT ;
    PORT
      LAYER M4 ;
      RECT 0.000 17.988 0.072 18.012 ;
    END
  END rw0_rd_out[111]
  PIN rw0_rd_out[112]
    DIRECTION OUTPUT ;
    USE SIGNAL ;
    SHAPE ABUTMENT ;
    PORT
      LAYER M4 ;
      RECT 45.234 17.988 45.306 18.012 ;
    END
  END rw0_rd_out[112]
  PIN rw0_rd_out[113]
    DIRECTION OUTPUT ;
    USE SIGNAL ;
    SHAPE ABUTMENT ;
    PORT
      LAYER M4 ;
      RECT 0.000 18.132 0.072 18.156 ;
    END
  END rw0_rd_out[113]
  PIN rw0_rd_out[114]
    DIRECTION OUTPUT ;
    USE SIGNAL ;
    SHAPE ABUTMENT ;
    PORT
      LAYER M4 ;
      RECT 45.234 18.132 45.306 18.156 ;
    END
  END rw0_rd_out[114]
  PIN rw0_rd_out[115]
    DIRECTION OUTPUT ;
    USE SIGNAL ;
    SHAPE ABUTMENT ;
    PORT
      LAYER M4 ;
      RECT 0.000 18.276 0.072 18.300 ;
    END
  END rw0_rd_out[115]
  PIN rw0_rd_out[116]
    DIRECTION OUTPUT ;
    USE SIGNAL ;
    SHAPE ABUTMENT ;
    PORT
      LAYER M4 ;
      RECT 45.234 18.276 45.306 18.300 ;
    END
  END rw0_rd_out[116]
  PIN rw0_rd_out[117]
    DIRECTION OUTPUT ;
    USE SIGNAL ;
    SHAPE ABUTMENT ;
    PORT
      LAYER M4 ;
      RECT 0.000 18.420 0.072 18.444 ;
    END
  END rw0_rd_out[117]
  PIN rw0_rd_out[118]
    DIRECTION OUTPUT ;
    USE SIGNAL ;
    SHAPE ABUTMENT ;
    PORT
      LAYER M4 ;
      RECT 45.234 18.420 45.306 18.444 ;
    END
  END rw0_rd_out[118]
  PIN rw0_rd_out[119]
    DIRECTION OUTPUT ;
    USE SIGNAL ;
    SHAPE ABUTMENT ;
    PORT
      LAYER M4 ;
      RECT 0.000 18.564 0.072 18.588 ;
    END
  END rw0_rd_out[119]
  PIN rw0_rd_out[120]
    DIRECTION OUTPUT ;
    USE SIGNAL ;
    SHAPE ABUTMENT ;
    PORT
      LAYER M4 ;
      RECT 45.234 18.564 45.306 18.588 ;
    END
  END rw0_rd_out[120]
  PIN rw0_rd_out[121]
    DIRECTION OUTPUT ;
    USE SIGNAL ;
    SHAPE ABUTMENT ;
    PORT
      LAYER M4 ;
      RECT 0.000 18.708 0.072 18.732 ;
    END
  END rw0_rd_out[121]
  PIN rw0_rd_out[122]
    DIRECTION OUTPUT ;
    USE SIGNAL ;
    SHAPE ABUTMENT ;
    PORT
      LAYER M4 ;
      RECT 45.234 18.708 45.306 18.732 ;
    END
  END rw0_rd_out[122]
  PIN rw0_rd_out[123]
    DIRECTION OUTPUT ;
    USE SIGNAL ;
    SHAPE ABUTMENT ;
    PORT
      LAYER M4 ;
      RECT 0.000 18.852 0.072 18.876 ;
    END
  END rw0_rd_out[123]
  PIN rw0_rd_out[124]
    DIRECTION OUTPUT ;
    USE SIGNAL ;
    SHAPE ABUTMENT ;
    PORT
      LAYER M4 ;
      RECT 45.234 18.852 45.306 18.876 ;
    END
  END rw0_rd_out[124]
  PIN rw0_rd_out[125]
    DIRECTION OUTPUT ;
    USE SIGNAL ;
    SHAPE ABUTMENT ;
    PORT
      LAYER M4 ;
      RECT 0.000 18.996 0.072 19.020 ;
    END
  END rw0_rd_out[125]
  PIN rw0_rd_out[126]
    DIRECTION OUTPUT ;
    USE SIGNAL ;
    SHAPE ABUTMENT ;
    PORT
      LAYER M4 ;
      RECT 45.234 18.996 45.306 19.020 ;
    END
  END rw0_rd_out[126]
  PIN rw0_rd_out[127]
    DIRECTION OUTPUT ;
    USE SIGNAL ;
    SHAPE ABUTMENT ;
    PORT
      LAYER M4 ;
      RECT 0.000 19.140 0.072 19.164 ;
    END
  END rw0_rd_out[127]
  PIN VDD
    DIRECTION INOUT ;
    USE POWER ;
    PORT
      LAYER M4 ;
      RECT 0.054 0.012 45.252 0.036 ;
      RECT 0.054 0.108 45.252 0.132 ;
      RECT 0.054 0.204 45.252 0.228 ;
      RECT 0.054 0.300 45.252 0.324 ;
      RECT 0.054 0.396 45.252 0.420 ;
      RECT 0.054 0.492 45.252 0.516 ;
      RECT 0.054 0.588 45.252 0.612 ;
      RECT 0.054 0.684 45.252 0.708 ;
      RECT 0.054 0.780 45.252 0.804 ;
      RECT 0.054 0.876 45.252 0.900 ;
      RECT 0.054 0.972 45.252 0.996 ;
      RECT 0.054 1.068 45.252 1.092 ;
      RECT 0.054 1.164 45.252 1.188 ;
      RECT 0.054 1.260 45.252 1.284 ;
      RECT 0.054 1.356 45.252 1.380 ;
      RECT 0.054 1.452 45.252 1.476 ;
      RECT 0.054 1.548 45.252 1.572 ;
      RECT 0.054 1.644 45.252 1.668 ;
      RECT 0.054 1.740 45.252 1.764 ;
      RECT 0.054 1.836 45.252 1.860 ;
      RECT 0.054 1.932 45.252 1.956 ;
      RECT 0.054 2.028 45.252 2.052 ;
      RECT 0.054 2.124 45.252 2.148 ;
      RECT 0.054 2.220 45.252 2.244 ;
      RECT 0.054 2.316 45.252 2.340 ;
      RECT 0.054 2.412 45.252 2.436 ;
      RECT 0.054 2.508 45.252 2.532 ;
      RECT 0.054 2.604 45.252 2.628 ;
      RECT 0.054 2.700 45.252 2.724 ;
      RECT 0.054 2.796 45.252 2.820 ;
      RECT 0.054 2.892 45.252 2.916 ;
      RECT 0.054 2.988 45.252 3.012 ;
      RECT 0.054 3.084 45.252 3.108 ;
      RECT 0.054 3.180 45.252 3.204 ;
      RECT 0.054 3.276 45.252 3.300 ;
      RECT 0.054 3.372 45.252 3.396 ;
      RECT 0.054 3.468 45.252 3.492 ;
      RECT 0.054 3.564 45.252 3.588 ;
      RECT 0.054 3.660 45.252 3.684 ;
      RECT 0.054 3.756 45.252 3.780 ;
      RECT 0.054 3.852 45.252 3.876 ;
      RECT 0.054 3.948 45.252 3.972 ;
      RECT 0.054 4.044 45.252 4.068 ;
      RECT 0.054 4.140 45.252 4.164 ;
      RECT 0.054 4.236 45.252 4.260 ;
      RECT 0.054 4.332 45.252 4.356 ;
      RECT 0.054 4.428 45.252 4.452 ;
      RECT 0.054 4.524 45.252 4.548 ;
      RECT 0.054 4.620 45.252 4.644 ;
      RECT 0.054 4.716 45.252 4.740 ;
      RECT 0.054 4.812 45.252 4.836 ;
      RECT 0.054 4.908 45.252 4.932 ;
      RECT 0.054 5.004 45.252 5.028 ;
      RECT 0.054 5.100 45.252 5.124 ;
      RECT 0.054 5.196 45.252 5.220 ;
      RECT 0.054 5.292 45.252 5.316 ;
      RECT 0.054 5.388 45.252 5.412 ;
      RECT 0.054 5.484 45.252 5.508 ;
      RECT 0.054 5.580 45.252 5.604 ;
      RECT 0.054 5.676 45.252 5.700 ;
      RECT 0.054 5.772 45.252 5.796 ;
      RECT 0.054 5.868 45.252 5.892 ;
      RECT 0.054 5.964 45.252 5.988 ;
      RECT 0.054 6.060 45.252 6.084 ;
      RECT 0.054 6.156 45.252 6.180 ;
      RECT 0.054 6.252 45.252 6.276 ;
      RECT 0.054 6.348 45.252 6.372 ;
      RECT 0.054 6.444 45.252 6.468 ;
      RECT 0.054 6.540 45.252 6.564 ;
      RECT 0.054 6.636 45.252 6.660 ;
      RECT 0.054 6.732 45.252 6.756 ;
      RECT 0.054 6.828 45.252 6.852 ;
      RECT 0.054 6.924 45.252 6.948 ;
      RECT 0.054 7.020 45.252 7.044 ;
      RECT 0.054 7.116 45.252 7.140 ;
      RECT 0.054 7.212 45.252 7.236 ;
      RECT 0.054 7.308 45.252 7.332 ;
      RECT 0.054 7.404 45.252 7.428 ;
      RECT 0.054 7.500 45.252 7.524 ;
      RECT 0.054 7.596 45.252 7.620 ;
      RECT 0.054 7.692 45.252 7.716 ;
      RECT 0.054 7.788 45.252 7.812 ;
      RECT 0.054 7.884 45.252 7.908 ;
      RECT 0.054 7.980 45.252 8.004 ;
      RECT 0.054 8.076 45.252 8.100 ;
      RECT 0.054 8.172 45.252 8.196 ;
      RECT 0.054 8.268 45.252 8.292 ;
      RECT 0.054 8.364 45.252 8.388 ;
      RECT 0.054 8.460 45.252 8.484 ;
      RECT 0.054 8.556 45.252 8.580 ;
      RECT 0.054 8.652 45.252 8.676 ;
      RECT 0.054 8.748 45.252 8.772 ;
      RECT 0.054 8.844 45.252 8.868 ;
      RECT 0.054 8.940 45.252 8.964 ;
      RECT 0.054 9.036 45.252 9.060 ;
      RECT 0.054 9.132 45.252 9.156 ;
      RECT 0.054 9.228 45.252 9.252 ;
      RECT 0.054 9.324 45.252 9.348 ;
      RECT 0.054 9.420 45.252 9.444 ;
      RECT 0.054 9.516 45.252 9.540 ;
      RECT 0.054 9.612 45.252 9.636 ;
      RECT 0.054 9.708 45.252 9.732 ;
      RECT 0.054 9.804 45.252 9.828 ;
      RECT 0.054 9.900 45.252 9.924 ;
      RECT 0.054 9.996 45.252 10.020 ;
      RECT 0.054 10.092 45.252 10.116 ;
      RECT 0.054 10.188 45.252 10.212 ;
      RECT 0.054 10.284 45.252 10.308 ;
      RECT 0.054 10.380 45.252 10.404 ;
      RECT 0.054 10.476 45.252 10.500 ;
      RECT 0.054 10.572 45.252 10.596 ;
      RECT 0.054 10.668 45.252 10.692 ;
      RECT 0.054 10.764 45.252 10.788 ;
      RECT 0.054 10.860 45.252 10.884 ;
      RECT 0.054 10.956 45.252 10.980 ;
      RECT 0.054 11.052 45.252 11.076 ;
      RECT 0.054 11.148 45.252 11.172 ;
      RECT 0.054 11.244 45.252 11.268 ;
      RECT 0.054 11.340 45.252 11.364 ;
      RECT 0.054 11.436 45.252 11.460 ;
      RECT 0.054 11.532 45.252 11.556 ;
      RECT 0.054 11.628 45.252 11.652 ;
      RECT 0.054 11.724 45.252 11.748 ;
      RECT 0.054 11.820 45.252 11.844 ;
      RECT 0.054 11.916 45.252 11.940 ;
      RECT 0.054 12.012 45.252 12.036 ;
      RECT 0.054 12.108 45.252 12.132 ;
      RECT 0.054 12.204 45.252 12.228 ;
      RECT 0.054 12.300 45.252 12.324 ;
      RECT 0.054 12.396 45.252 12.420 ;
      RECT 0.054 12.492 45.252 12.516 ;
      RECT 0.054 12.588 45.252 12.612 ;
      RECT 0.054 12.684 45.252 12.708 ;
      RECT 0.054 12.780 45.252 12.804 ;
      RECT 0.054 12.876 45.252 12.900 ;
      RECT 0.054 12.972 45.252 12.996 ;
      RECT 0.054 13.068 45.252 13.092 ;
      RECT 0.054 13.164 45.252 13.188 ;
      RECT 0.054 13.260 45.252 13.284 ;
      RECT 0.054 13.356 45.252 13.380 ;
      RECT 0.054 13.452 45.252 13.476 ;
      RECT 0.054 13.548 45.252 13.572 ;
      RECT 0.054 13.644 45.252 13.668 ;
      RECT 0.054 13.740 45.252 13.764 ;
      RECT 0.054 13.836 45.252 13.860 ;
      RECT 0.054 13.932 45.252 13.956 ;
      RECT 0.054 14.028 45.252 14.052 ;
      RECT 0.054 14.124 45.252 14.148 ;
      RECT 0.054 14.220 45.252 14.244 ;
      RECT 0.054 14.316 45.252 14.340 ;
      RECT 0.054 14.412 45.252 14.436 ;
      RECT 0.054 14.508 45.252 14.532 ;
      RECT 0.054 14.604 45.252 14.628 ;
      RECT 0.054 14.700 45.252 14.724 ;
      RECT 0.054 14.796 45.252 14.820 ;
      RECT 0.054 14.892 45.252 14.916 ;
      RECT 0.054 14.988 45.252 15.012 ;
      RECT 0.054 15.084 45.252 15.108 ;
      RECT 0.054 15.180 45.252 15.204 ;
      RECT 0.054 15.276 45.252 15.300 ;
      RECT 0.054 15.372 45.252 15.396 ;
      RECT 0.054 15.468 45.252 15.492 ;
      RECT 0.054 15.564 45.252 15.588 ;
      RECT 0.054 15.660 45.252 15.684 ;
      RECT 0.054 15.756 45.252 15.780 ;
      RECT 0.054 15.852 45.252 15.876 ;
      RECT 0.054 15.948 45.252 15.972 ;
      RECT 0.054 16.044 45.252 16.068 ;
      RECT 0.054 16.140 45.252 16.164 ;
      RECT 0.054 16.236 45.252 16.260 ;
      RECT 0.054 16.332 45.252 16.356 ;
      RECT 0.054 16.428 45.252 16.452 ;
      RECT 0.054 16.524 45.252 16.548 ;
      RECT 0.054 16.620 45.252 16.644 ;
      RECT 0.054 16.716 45.252 16.740 ;
      RECT 0.054 16.812 45.252 16.836 ;
      RECT 0.054 16.908 45.252 16.932 ;
      RECT 0.054 17.004 45.252 17.028 ;
      RECT 0.054 17.100 45.252 17.124 ;
      RECT 0.054 17.196 45.252 17.220 ;
      RECT 0.054 17.292 45.252 17.316 ;
      RECT 0.054 17.388 45.252 17.412 ;
      RECT 0.054 17.484 45.252 17.508 ;
      RECT 0.054 17.580 45.252 17.604 ;
      RECT 0.054 17.676 45.252 17.700 ;
      RECT 0.054 17.772 45.252 17.796 ;
      RECT 0.054 17.868 45.252 17.892 ;
      RECT 0.054 17.964 45.252 17.988 ;
      RECT 0.054 18.060 45.252 18.084 ;
      RECT 0.054 18.156 45.252 18.180 ;
      RECT 0.054 18.252 45.252 18.276 ;
      RECT 0.054 18.348 45.252 18.372 ;
      RECT 0.054 18.444 45.252 18.468 ;
      RECT 0.054 18.540 45.252 18.564 ;
      RECT 0.054 18.636 45.252 18.660 ;
      RECT 0.054 18.732 45.252 18.756 ;
      RECT 0.054 18.828 45.252 18.852 ;
      RECT 0.054 18.924 45.252 18.948 ;
      RECT 0.054 19.020 45.252 19.044 ;
      RECT 0.054 19.116 45.252 19.140 ;
      RECT 0.054 19.212 45.252 19.236 ;
      RECT 0.054 19.308 45.252 19.332 ;
      RECT 0.054 19.404 45.252 19.428 ;
      RECT 0.054 19.500 45.252 19.524 ;
      RECT 0.054 19.596 45.252 19.620 ;
      RECT 0.054 19.692 45.252 19.716 ;
      RECT 0.054 19.788 45.252 19.812 ;
      RECT 0.054 19.884 45.252 19.908 ;
      RECT 0.054 19.980 45.252 20.004 ;
      RECT 0.054 20.076 45.252 20.100 ;
      RECT 0.054 20.172 45.252 20.196 ;
      RECT 0.054 20.268 45.252 20.292 ;
      RECT 0.054 20.364 45.252 20.388 ;
      RECT 0.054 20.460 45.252 20.484 ;
      RECT 0.054 20.556 45.252 20.580 ;
      RECT 0.054 20.652 45.252 20.676 ;
      RECT 0.054 20.748 45.252 20.772 ;
      RECT 0.054 20.844 45.252 20.868 ;
      RECT 0.054 20.940 45.252 20.964 ;
      RECT 0.054 21.036 45.252 21.060 ;
      RECT 0.054 21.132 45.252 21.156 ;
      RECT 0.054 21.228 45.252 21.252 ;
      RECT 0.054 21.324 45.252 21.348 ;
      RECT 0.054 21.420 45.252 21.444 ;
      RECT 0.054 21.516 45.252 21.540 ;
      RECT 0.054 21.612 45.252 21.636 ;
      RECT 0.054 21.708 45.252 21.732 ;
      RECT 0.054 21.804 45.252 21.828 ;
      RECT 0.054 21.900 45.252 21.924 ;
      RECT 0.054 21.996 45.252 22.020 ;
      RECT 0.054 22.092 45.252 22.116 ;
      RECT 0.054 22.188 45.252 22.212 ;
      RECT 0.054 22.284 45.252 22.308 ;
      RECT 0.054 22.380 45.252 22.404 ;
      RECT 0.054 22.476 45.252 22.500 ;
      RECT 0.054 22.572 45.252 22.596 ;
    END
  END VDD
  PIN VSS
    DIRECTION INOUT ;
    USE GROUND ;
    PORT
      LAYER M4 ;
      RECT 0.054 0.060 45.252 0.084 ;
      RECT 0.054 0.156 45.252 0.180 ;
      RECT 0.054 0.252 45.252 0.276 ;
      RECT 0.054 0.348 45.252 0.372 ;
      RECT 0.054 0.444 45.252 0.468 ;
      RECT 0.054 0.540 45.252 0.564 ;
      RECT 0.054 0.636 45.252 0.660 ;
      RECT 0.054 0.732 45.252 0.756 ;
      RECT 0.054 0.828 45.252 0.852 ;
      RECT 0.054 0.924 45.252 0.948 ;
      RECT 0.054 1.020 45.252 1.044 ;
      RECT 0.054 1.116 45.252 1.140 ;
      RECT 0.054 1.212 45.252 1.236 ;
      RECT 0.054 1.308 45.252 1.332 ;
      RECT 0.054 1.404 45.252 1.428 ;
      RECT 0.054 1.500 45.252 1.524 ;
      RECT 0.054 1.596 45.252 1.620 ;
      RECT 0.054 1.692 45.252 1.716 ;
      RECT 0.054 1.788 45.252 1.812 ;
      RECT 0.054 1.884 45.252 1.908 ;
      RECT 0.054 1.980 45.252 2.004 ;
      RECT 0.054 2.076 45.252 2.100 ;
      RECT 0.054 2.172 45.252 2.196 ;
      RECT 0.054 2.268 45.252 2.292 ;
      RECT 0.054 2.364 45.252 2.388 ;
      RECT 0.054 2.460 45.252 2.484 ;
      RECT 0.054 2.556 45.252 2.580 ;
      RECT 0.054 2.652 45.252 2.676 ;
      RECT 0.054 2.748 45.252 2.772 ;
      RECT 0.054 2.844 45.252 2.868 ;
      RECT 0.054 2.940 45.252 2.964 ;
      RECT 0.054 3.036 45.252 3.060 ;
      RECT 0.054 3.132 45.252 3.156 ;
      RECT 0.054 3.228 45.252 3.252 ;
      RECT 0.054 3.324 45.252 3.348 ;
      RECT 0.054 3.420 45.252 3.444 ;
      RECT 0.054 3.516 45.252 3.540 ;
      RECT 0.054 3.612 45.252 3.636 ;
      RECT 0.054 3.708 45.252 3.732 ;
      RECT 0.054 3.804 45.252 3.828 ;
      RECT 0.054 3.900 45.252 3.924 ;
      RECT 0.054 3.996 45.252 4.020 ;
      RECT 0.054 4.092 45.252 4.116 ;
      RECT 0.054 4.188 45.252 4.212 ;
      RECT 0.054 4.284 45.252 4.308 ;
      RECT 0.054 4.380 45.252 4.404 ;
      RECT 0.054 4.476 45.252 4.500 ;
      RECT 0.054 4.572 45.252 4.596 ;
      RECT 0.054 4.668 45.252 4.692 ;
      RECT 0.054 4.764 45.252 4.788 ;
      RECT 0.054 4.860 45.252 4.884 ;
      RECT 0.054 4.956 45.252 4.980 ;
      RECT 0.054 5.052 45.252 5.076 ;
      RECT 0.054 5.148 45.252 5.172 ;
      RECT 0.054 5.244 45.252 5.268 ;
      RECT 0.054 5.340 45.252 5.364 ;
      RECT 0.054 5.436 45.252 5.460 ;
      RECT 0.054 5.532 45.252 5.556 ;
      RECT 0.054 5.628 45.252 5.652 ;
      RECT 0.054 5.724 45.252 5.748 ;
      RECT 0.054 5.820 45.252 5.844 ;
      RECT 0.054 5.916 45.252 5.940 ;
      RECT 0.054 6.012 45.252 6.036 ;
      RECT 0.054 6.108 45.252 6.132 ;
      RECT 0.054 6.204 45.252 6.228 ;
      RECT 0.054 6.300 45.252 6.324 ;
      RECT 0.054 6.396 45.252 6.420 ;
      RECT 0.054 6.492 45.252 6.516 ;
      RECT 0.054 6.588 45.252 6.612 ;
      RECT 0.054 6.684 45.252 6.708 ;
      RECT 0.054 6.780 45.252 6.804 ;
      RECT 0.054 6.876 45.252 6.900 ;
      RECT 0.054 6.972 45.252 6.996 ;
      RECT 0.054 7.068 45.252 7.092 ;
      RECT 0.054 7.164 45.252 7.188 ;
      RECT 0.054 7.260 45.252 7.284 ;
      RECT 0.054 7.356 45.252 7.380 ;
      RECT 0.054 7.452 45.252 7.476 ;
      RECT 0.054 7.548 45.252 7.572 ;
      RECT 0.054 7.644 45.252 7.668 ;
      RECT 0.054 7.740 45.252 7.764 ;
      RECT 0.054 7.836 45.252 7.860 ;
      RECT 0.054 7.932 45.252 7.956 ;
      RECT 0.054 8.028 45.252 8.052 ;
      RECT 0.054 8.124 45.252 8.148 ;
      RECT 0.054 8.220 45.252 8.244 ;
      RECT 0.054 8.316 45.252 8.340 ;
      RECT 0.054 8.412 45.252 8.436 ;
      RECT 0.054 8.508 45.252 8.532 ;
      RECT 0.054 8.604 45.252 8.628 ;
      RECT 0.054 8.700 45.252 8.724 ;
      RECT 0.054 8.796 45.252 8.820 ;
      RECT 0.054 8.892 45.252 8.916 ;
      RECT 0.054 8.988 45.252 9.012 ;
      RECT 0.054 9.084 45.252 9.108 ;
      RECT 0.054 9.180 45.252 9.204 ;
      RECT 0.054 9.276 45.252 9.300 ;
      RECT 0.054 9.372 45.252 9.396 ;
      RECT 0.054 9.468 45.252 9.492 ;
      RECT 0.054 9.564 45.252 9.588 ;
      RECT 0.054 9.660 45.252 9.684 ;
      RECT 0.054 9.756 45.252 9.780 ;
      RECT 0.054 9.852 45.252 9.876 ;
      RECT 0.054 9.948 45.252 9.972 ;
      RECT 0.054 10.044 45.252 10.068 ;
      RECT 0.054 10.140 45.252 10.164 ;
      RECT 0.054 10.236 45.252 10.260 ;
      RECT 0.054 10.332 45.252 10.356 ;
      RECT 0.054 10.428 45.252 10.452 ;
      RECT 0.054 10.524 45.252 10.548 ;
      RECT 0.054 10.620 45.252 10.644 ;
      RECT 0.054 10.716 45.252 10.740 ;
      RECT 0.054 10.812 45.252 10.836 ;
      RECT 0.054 10.908 45.252 10.932 ;
      RECT 0.054 11.004 45.252 11.028 ;
      RECT 0.054 11.100 45.252 11.124 ;
      RECT 0.054 11.196 45.252 11.220 ;
      RECT 0.054 11.292 45.252 11.316 ;
      RECT 0.054 11.388 45.252 11.412 ;
      RECT 0.054 11.484 45.252 11.508 ;
      RECT 0.054 11.580 45.252 11.604 ;
      RECT 0.054 11.676 45.252 11.700 ;
      RECT 0.054 11.772 45.252 11.796 ;
      RECT 0.054 11.868 45.252 11.892 ;
      RECT 0.054 11.964 45.252 11.988 ;
      RECT 0.054 12.060 45.252 12.084 ;
      RECT 0.054 12.156 45.252 12.180 ;
      RECT 0.054 12.252 45.252 12.276 ;
      RECT 0.054 12.348 45.252 12.372 ;
      RECT 0.054 12.444 45.252 12.468 ;
      RECT 0.054 12.540 45.252 12.564 ;
      RECT 0.054 12.636 45.252 12.660 ;
      RECT 0.054 12.732 45.252 12.756 ;
      RECT 0.054 12.828 45.252 12.852 ;
      RECT 0.054 12.924 45.252 12.948 ;
      RECT 0.054 13.020 45.252 13.044 ;
      RECT 0.054 13.116 45.252 13.140 ;
      RECT 0.054 13.212 45.252 13.236 ;
      RECT 0.054 13.308 45.252 13.332 ;
      RECT 0.054 13.404 45.252 13.428 ;
      RECT 0.054 13.500 45.252 13.524 ;
      RECT 0.054 13.596 45.252 13.620 ;
      RECT 0.054 13.692 45.252 13.716 ;
      RECT 0.054 13.788 45.252 13.812 ;
      RECT 0.054 13.884 45.252 13.908 ;
      RECT 0.054 13.980 45.252 14.004 ;
      RECT 0.054 14.076 45.252 14.100 ;
      RECT 0.054 14.172 45.252 14.196 ;
      RECT 0.054 14.268 45.252 14.292 ;
      RECT 0.054 14.364 45.252 14.388 ;
      RECT 0.054 14.460 45.252 14.484 ;
      RECT 0.054 14.556 45.252 14.580 ;
      RECT 0.054 14.652 45.252 14.676 ;
      RECT 0.054 14.748 45.252 14.772 ;
      RECT 0.054 14.844 45.252 14.868 ;
      RECT 0.054 14.940 45.252 14.964 ;
      RECT 0.054 15.036 45.252 15.060 ;
      RECT 0.054 15.132 45.252 15.156 ;
      RECT 0.054 15.228 45.252 15.252 ;
      RECT 0.054 15.324 45.252 15.348 ;
      RECT 0.054 15.420 45.252 15.444 ;
      RECT 0.054 15.516 45.252 15.540 ;
      RECT 0.054 15.612 45.252 15.636 ;
      RECT 0.054 15.708 45.252 15.732 ;
      RECT 0.054 15.804 45.252 15.828 ;
      RECT 0.054 15.900 45.252 15.924 ;
      RECT 0.054 15.996 45.252 16.020 ;
      RECT 0.054 16.092 45.252 16.116 ;
      RECT 0.054 16.188 45.252 16.212 ;
      RECT 0.054 16.284 45.252 16.308 ;
      RECT 0.054 16.380 45.252 16.404 ;
      RECT 0.054 16.476 45.252 16.500 ;
      RECT 0.054 16.572 45.252 16.596 ;
      RECT 0.054 16.668 45.252 16.692 ;
      RECT 0.054 16.764 45.252 16.788 ;
      RECT 0.054 16.860 45.252 16.884 ;
      RECT 0.054 16.956 45.252 16.980 ;
      RECT 0.054 17.052 45.252 17.076 ;
      RECT 0.054 17.148 45.252 17.172 ;
      RECT 0.054 17.244 45.252 17.268 ;
      RECT 0.054 17.340 45.252 17.364 ;
      RECT 0.054 17.436 45.252 17.460 ;
      RECT 0.054 17.532 45.252 17.556 ;
      RECT 0.054 17.628 45.252 17.652 ;
      RECT 0.054 17.724 45.252 17.748 ;
      RECT 0.054 17.820 45.252 17.844 ;
      RECT 0.054 17.916 45.252 17.940 ;
      RECT 0.054 18.012 45.252 18.036 ;
      RECT 0.054 18.108 45.252 18.132 ;
      RECT 0.054 18.204 45.252 18.228 ;
      RECT 0.054 18.300 45.252 18.324 ;
      RECT 0.054 18.396 45.252 18.420 ;
      RECT 0.054 18.492 45.252 18.516 ;
      RECT 0.054 18.588 45.252 18.612 ;
      RECT 0.054 18.684 45.252 18.708 ;
      RECT 0.054 18.780 45.252 18.804 ;
      RECT 0.054 18.876 45.252 18.900 ;
      RECT 0.054 18.972 45.252 18.996 ;
      RECT 0.054 19.068 45.252 19.092 ;
      RECT 0.054 19.164 45.252 19.188 ;
      RECT 0.054 19.260 45.252 19.284 ;
      RECT 0.054 19.356 45.252 19.380 ;
      RECT 0.054 19.452 45.252 19.476 ;
      RECT 0.054 19.548 45.252 19.572 ;
      RECT 0.054 19.644 45.252 19.668 ;
      RECT 0.054 19.740 45.252 19.764 ;
      RECT 0.054 19.836 45.252 19.860 ;
      RECT 0.054 19.932 45.252 19.956 ;
      RECT 0.054 20.028 45.252 20.052 ;
      RECT 0.054 20.124 45.252 20.148 ;
      RECT 0.054 20.220 45.252 20.244 ;
      RECT 0.054 20.316 45.252 20.340 ;
      RECT 0.054 20.412 45.252 20.436 ;
      RECT 0.054 20.508 45.252 20.532 ;
      RECT 0.054 20.604 45.252 20.628 ;
      RECT 0.054 20.700 45.252 20.724 ;
      RECT 0.054 20.796 45.252 20.820 ;
      RECT 0.054 20.892 45.252 20.916 ;
      RECT 0.054 20.988 45.252 21.012 ;
      RECT 0.054 21.084 45.252 21.108 ;
      RECT 0.054 21.180 45.252 21.204 ;
      RECT 0.054 21.276 45.252 21.300 ;
      RECT 0.054 21.372 45.252 21.396 ;
      RECT 0.054 21.468 45.252 21.492 ;
      RECT 0.054 21.564 45.252 21.588 ;
      RECT 0.054 21.660 45.252 21.684 ;
      RECT 0.054 21.756 45.252 21.780 ;
      RECT 0.054 21.852 45.252 21.876 ;
      RECT 0.054 21.948 45.252 21.972 ;
      RECT 0.054 22.044 45.252 22.068 ;
      RECT 0.054 22.140 45.252 22.164 ;
      RECT 0.054 22.236 45.252 22.260 ;
      RECT 0.054 22.332 45.252 22.356 ;
      RECT 0.054 22.428 45.252 22.452 ;
      RECT 0.054 22.524 45.252 22.548 ;
      RECT 0.054 22.620 45.252 22.644 ;
    END
  END VSS
  OBS
    LAYER M1 ;
      RECT 0.000 0.000 45.306 22.680 ;
    LAYER M2 ;
      RECT 0.000 0.000 45.306 22.680 ;
    LAYER M3 ;
      RECT 0.000 0.000 45.306 22.680 ;
  END
END fakeram7_16x128
END LIBRARY
